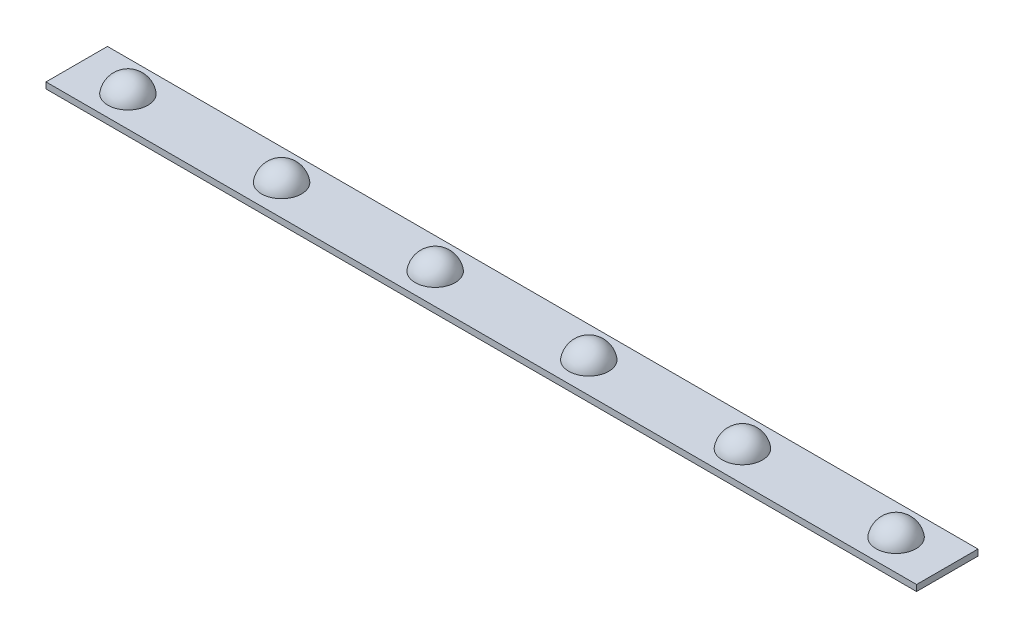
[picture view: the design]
ISO-10303-21;
HEADER;
FILE_DESCRIPTION(('STEP AP214'),'2;1');
FILE_NAME('part.step','',(''),(''),'','','');
FILE_SCHEMA(('AUTOMOTIVE_DESIGN { 1 0 10303 214 1 1 1 1 }'));
ENDSEC;
DATA;
#1=APPLICATION_CONTEXT('core data for automotive mechanical design processes');
#2=APPLICATION_PROTOCOL_DEFINITION('international standard','automotive_design',2000,#1);
#3=PRODUCT_CONTEXT('',#1,'mechanical');
#4=PRODUCT('Part','Part','',(#3));
#5=PRODUCT_RELATED_PRODUCT_CATEGORY('part','',(#4));
#6=PRODUCT_DEFINITION_FORMATION('','',#4);
#7=PRODUCT_DEFINITION_CONTEXT('part definition',#1,'design');
#8=PRODUCT_DEFINITION('design','',#6,#7);
#9=PRODUCT_DEFINITION_SHAPE('','',#8);
#10=(LENGTH_UNIT() NAMED_UNIT(*) SI_UNIT(.MILLI.,.METRE.));
#11=(NAMED_UNIT(*) PLANE_ANGLE_UNIT() SI_UNIT($,.RADIAN.));
#12=(NAMED_UNIT(*) SI_UNIT($,.STERADIAN.) SOLID_ANGLE_UNIT());
#13=UNCERTAINTY_MEASURE_WITH_UNIT(LENGTH_MEASURE(1.E-05),#10,'distance_accuracy_value','');
#14=(GEOMETRIC_REPRESENTATION_CONTEXT(3) GLOBAL_UNCERTAINTY_ASSIGNED_CONTEXT((#13)) GLOBAL_UNIT_ASSIGNED_CONTEXT((#10,
#11,#12)) REPRESENTATION_CONTEXT('',''));
#15=CARTESIAN_POINT('',(0.,0.,0.));
#16=DIRECTION('',(0.,0.,1.));
#17=DIRECTION('',(1.,0.,0.));
#18=AXIS2_PLACEMENT_3D('',#15,#16,#17);
#19=CARTESIAN_POINT('',(-243.713,-19.5553717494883,3.9624));
#20=DIRECTION('',(0.,1.,0.));
#21=DIRECTION('',(0.,0.,1.));
#22=AXIS2_PLACEMENT_3D('',#19,#20,#21);
#23=PLANE('',#22);
#24=CARTESIAN_POINT('',(-237.363,-19.5553717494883,2.63210155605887));
#25=CARTESIAN_POINT('',(-237.447190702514,-19.5553717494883,2.63210227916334));
#26=CARTESIAN_POINT('',(-237.531370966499,-19.5553717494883,2.62780900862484));
#27=CARTESIAN_POINT('',(-237.698898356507,-19.5553717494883,2.61069058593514));
#28=CARTESIAN_POINT('',(-237.782244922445,-19.5553717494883,2.5978600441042));
#29=CARTESIAN_POINT('',(-238.001164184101,-19.5553717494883,2.55261481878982));
#30=CARTESIAN_POINT('',(-238.135296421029,-19.5553717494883,2.51288252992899));
#31=CARTESIAN_POINT('',(-238.395079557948,-19.5553717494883,2.41143114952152));
#32=CARTESIAN_POINT('',(-238.520720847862,-19.5553717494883,2.3496876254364));
#33=CARTESIAN_POINT('',(-238.759809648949,-19.5553717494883,2.20600089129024));
#34=CARTESIAN_POINT('',(-238.873262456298,-19.5553717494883,2.12406650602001));
#35=CARTESIAN_POINT('',(-239.084770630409,-19.5553717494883,1.94233439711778));
#36=CARTESIAN_POINT('',(-239.18282968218,-19.5553717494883,1.84254096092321));
#37=CARTESIAN_POINT('',(-239.360814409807,-19.5553717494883,1.62789843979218));
#38=CARTESIAN_POINT('',(-239.440738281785,-19.5553717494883,1.51304785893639));
#39=CARTESIAN_POINT('',(-239.580172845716,-19.5553717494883,1.27155407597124));
#40=CARTESIAN_POINT('',(-239.639682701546,-19.5553717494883,1.14491039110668));
#41=CARTESIAN_POINT('',(-239.736594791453,-19.5553717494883,0.883432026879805));
#42=CARTESIAN_POINT('',(-239.77399744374,-19.5553717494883,0.748597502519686));
#43=CARTESIAN_POINT('',(-239.825634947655,-19.5553717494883,0.47456328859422));
#44=CARTESIAN_POINT('',(-239.839869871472,-19.5553717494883,0.335363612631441));
#45=CARTESIAN_POINT('',(-239.844768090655,-19.5553717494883,0.0565500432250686));
#46=CARTESIAN_POINT('',(-239.835431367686,-19.5553717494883,-0.0830638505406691));
#47=CARTESIAN_POINT('',(-239.793451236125,-19.5553717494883,-0.358742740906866));
#48=CARTESIAN_POINT('',(-239.760807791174,-19.5553717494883,-0.494807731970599));
#49=CARTESIAN_POINT('',(-239.673140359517,-19.5553717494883,-0.75952774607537));
#50=CARTESIAN_POINT('',(-239.61811609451,-19.5553717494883,-0.888182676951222));
#51=CARTESIAN_POINT('',(-239.487250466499,-19.5553717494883,-1.13442527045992));
#52=CARTESIAN_POINT('',(-239.411409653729,-19.5553717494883,-1.25201322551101));
#53=CARTESIAN_POINT('',(-239.241069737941,-19.5553717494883,-1.47278061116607));
#54=CARTESIAN_POINT('',(-239.146571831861,-19.5553717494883,-1.57596096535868));
#55=CARTESIAN_POINT('',(-238.941576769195,-19.5553717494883,-1.76500863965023));
#56=CARTESIAN_POINT('',(-238.831077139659,-19.5553717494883,-1.85087327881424));
#57=CARTESIAN_POINT('',(-238.597209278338,-19.5553717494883,-2.0028513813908));
#58=CARTESIAN_POINT('',(-238.473837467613,-19.5553717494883,-2.06895933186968));
#59=CARTESIAN_POINT('',(-238.217789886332,-19.5553717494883,-2.17947999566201));
#60=CARTESIAN_POINT('',(-238.085120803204,-19.5553717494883,-2.22390812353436));
#61=CARTESIAN_POINT('',(-237.853783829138,-19.5553717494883,-2.28025921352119));
#62=CARTESIAN_POINT('',(-237.75646039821,-19.5553717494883,-2.29787961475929));
#63=CARTESIAN_POINT('',(-237.560419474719,-19.5553717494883,-2.32139798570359));
#64=CARTESIAN_POINT('',(-237.461702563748,-19.5553717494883,-2.32730070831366));
#65=CARTESIAN_POINT('',(-237.278809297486,-19.5553717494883,-2.32730227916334));
#66=CARTESIAN_POINT('',(-237.194629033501,-19.5553717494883,-2.32300900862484));
#67=CARTESIAN_POINT('',(-237.027101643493,-19.5553717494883,-2.30589058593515));
#68=CARTESIAN_POINT('',(-236.943755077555,-19.5553717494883,-2.2930600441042));
#69=CARTESIAN_POINT('',(-236.724835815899,-19.5553717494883,-2.24781481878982));
#70=CARTESIAN_POINT('',(-236.590703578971,-19.5553717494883,-2.20808252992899));
#71=CARTESIAN_POINT('',(-236.330920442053,-19.5553717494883,-2.10663114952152));
#72=CARTESIAN_POINT('',(-236.205279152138,-19.5553717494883,-2.04488762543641));
#73=CARTESIAN_POINT('',(-235.966190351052,-19.5553717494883,-1.90120089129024));
#74=CARTESIAN_POINT('',(-235.852737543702,-19.5553717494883,-1.81926650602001));
#75=CARTESIAN_POINT('',(-235.641229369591,-19.5553717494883,-1.63753439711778));
#76=CARTESIAN_POINT('',(-235.54317031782,-19.5553717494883,-1.53774096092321));
#77=CARTESIAN_POINT('',(-235.365185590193,-19.5553717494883,-1.32309843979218));
#78=CARTESIAN_POINT('',(-235.285261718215,-19.5553717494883,-1.20824785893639));
#79=CARTESIAN_POINT('',(-235.145827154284,-19.5553717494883,-0.966754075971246));
#80=CARTESIAN_POINT('',(-235.086317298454,-19.5553717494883,-0.840110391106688));
#81=CARTESIAN_POINT('',(-234.989405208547,-19.5553717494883,-0.578632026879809));
#82=CARTESIAN_POINT('',(-234.952002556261,-19.5553717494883,-0.443797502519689));
#83=CARTESIAN_POINT('',(-234.900365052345,-19.5553717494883,-0.169763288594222));
#84=CARTESIAN_POINT('',(-234.886130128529,-19.5553717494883,-0.0305636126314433));
#85=CARTESIAN_POINT('',(-234.881231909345,-19.5553717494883,0.24824995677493));
#86=CARTESIAN_POINT('',(-234.890568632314,-19.5553717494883,0.387863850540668));
#87=CARTESIAN_POINT('',(-234.932548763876,-19.5553717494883,0.663542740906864));
#88=CARTESIAN_POINT('',(-234.965192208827,-19.5553717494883,0.799607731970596));
#89=CARTESIAN_POINT('',(-235.052859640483,-19.5553717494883,1.06432774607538));
#90=CARTESIAN_POINT('',(-235.10788390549,-19.5553717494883,1.19298267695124));
#91=CARTESIAN_POINT('',(-235.238749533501,-19.5553717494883,1.43922527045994));
#92=CARTESIAN_POINT('',(-235.314590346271,-19.5553717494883,1.55681322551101));
#93=CARTESIAN_POINT('',(-235.484930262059,-19.5553717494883,1.77758061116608));
#94=CARTESIAN_POINT('',(-235.579428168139,-19.5553717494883,1.88076096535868));
#95=CARTESIAN_POINT('',(-235.784423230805,-19.5553717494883,2.06980863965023));
#96=CARTESIAN_POINT('',(-235.894922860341,-19.5553717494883,2.15567327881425));
#97=CARTESIAN_POINT('',(-236.128790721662,-19.5553717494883,2.30765138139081));
#98=CARTESIAN_POINT('',(-236.252162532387,-19.5553717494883,2.37375933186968));
#99=CARTESIAN_POINT('',(-236.508210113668,-19.5553717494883,2.484279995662));
#100=CARTESIAN_POINT('',(-236.640879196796,-19.5553717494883,2.52870812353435));
#101=CARTESIAN_POINT('',(-236.872216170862,-19.5553717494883,2.58505921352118));
#102=CARTESIAN_POINT('',(-236.96953960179,-19.5553717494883,2.60267961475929));
#103=CARTESIAN_POINT('',(-237.165580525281,-19.5553717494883,2.62619798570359));
#104=CARTESIAN_POINT('',(-237.264297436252,-19.5553717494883,2.63210070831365));
#105=CARTESIAN_POINT('',(-237.363,-19.5553717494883,2.63210155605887));
#106=B_SPLINE_CURVE_WITH_KNOTS('',3,(#24,#25,#26,#27,#28,#29,#30,#31,#32,#33,#34,#35,#36,#37,
#38,#39,#40,#41,#42,#43,#44,#45,#46,#47,#48,#49,#50,#51,#52,#53,#54,#55,#56,#57,#58,#59,#60,#61,
#62,#63,#64,#65,#66,#67,#68,#69,#70,#71,#72,#73,#74,#75,#76,#77,#78,#79,#80,#81,#82,#83,#84,#85,
#86,#87,#88,#89,#90,#91,#92,#93,#94,#95,#96,#97,#98,#99,#100,#101,#102,#103,#104,#105),
.UNSPECIFIED.,.T.,.F.,(4,2,2,2,2,2,2,2,2,2,2,2,2,2,2,2,2,2,2,2,2,2,2,2,2,2,2,2,2,2,2,2,2,2,2,2,
2,2,2,2,4),(0.,0.252435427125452,0.505030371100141,0.922589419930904,1.34061341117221,
1.75845502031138,2.17619645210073,2.59397941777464,3.0117794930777,3.42957166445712,
3.8473625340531,4.26515372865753,4.6829455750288,5.10074261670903,5.51852861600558,
5.93628782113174,6.35411165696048,6.77205197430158,7.18969469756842,7.4857622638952,
7.7817097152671,8.03414514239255,8.28674008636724,8.70429913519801,9.12232312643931,
9.54016473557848,9.95790616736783,10.3756891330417,10.7934892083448,11.2112813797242,
11.6290722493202,12.0468634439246,12.4646552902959,12.8824523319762,13.3002383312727,
13.7179975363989,14.1358213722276,14.5537616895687,14.9714044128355,15.2674719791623,
15.5634194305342),.UNSPECIFIED.);
#107=CARTESIAN_POINT('',(-237.363,-19.5553717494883,2.63210155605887));
#108=VERTEX_POINT('',#107);
#109=EDGE_CURVE('E256',#108,#108,#106,.T.);
#110=ORIENTED_EDGE('',*,*,#109,.F.);
#111=EDGE_LOOP('',(#110));
#112=FACE_BOUND('',#111,.T.);
#113=CARTESIAN_POINT('',(-218.313,-19.5553717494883,-2.32730155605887));
#114=CARTESIAN_POINT('',(-218.228809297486,-19.5553717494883,-2.32730227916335));
#115=CARTESIAN_POINT('',(-218.144629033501,-19.5553717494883,-2.32300900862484));
#116=CARTESIAN_POINT('',(-217.977101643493,-19.5553717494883,-2.30589058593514));
#117=CARTESIAN_POINT('',(-217.893755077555,-19.5553717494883,-2.2930600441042));
#118=CARTESIAN_POINT('',(-217.674835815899,-19.5553717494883,-2.24781481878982));
#119=CARTESIAN_POINT('',(-217.540703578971,-19.5553717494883,-2.20808252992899));
#120=CARTESIAN_POINT('',(-217.280920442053,-19.5553717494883,-2.10663114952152));
#121=CARTESIAN_POINT('',(-217.155279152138,-19.5553717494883,-2.0448876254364));
#122=CARTESIAN_POINT('',(-216.916190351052,-19.5553717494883,-1.90120089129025));
#123=CARTESIAN_POINT('',(-216.802737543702,-19.5553717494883,-1.81926650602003));
#124=CARTESIAN_POINT('',(-216.591229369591,-19.5553717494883,-1.6375343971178));
#125=CARTESIAN_POINT('',(-216.49317031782,-19.5553717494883,-1.53774096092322));
#126=CARTESIAN_POINT('',(-216.315185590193,-19.5553717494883,-1.32309843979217));
#127=CARTESIAN_POINT('',(-216.235261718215,-19.5553717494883,-1.20824785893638));
#128=CARTESIAN_POINT('',(-216.095827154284,-19.5553717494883,-0.966754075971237));
#129=CARTESIAN_POINT('',(-216.036317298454,-19.5553717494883,-0.840110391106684));
#130=CARTESIAN_POINT('',(-215.939405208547,-19.5553717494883,-0.578632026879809));
#131=CARTESIAN_POINT('',(-215.902002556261,-19.5553717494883,-0.443797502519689));
#132=CARTESIAN_POINT('',(-215.850365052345,-19.5553717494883,-0.169763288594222));
#133=CARTESIAN_POINT('',(-215.836130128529,-19.5553717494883,-0.0305636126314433));
#134=CARTESIAN_POINT('',(-215.831231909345,-19.5553717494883,0.248249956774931));
#135=CARTESIAN_POINT('',(-215.840568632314,-19.5553717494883,0.387863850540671));
#136=CARTESIAN_POINT('',(-215.882548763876,-19.5553717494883,0.663542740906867));
#137=CARTESIAN_POINT('',(-215.915192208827,-19.5553717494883,0.799607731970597));
#138=CARTESIAN_POINT('',(-216.002859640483,-19.5553717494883,1.06432774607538));
#139=CARTESIAN_POINT('',(-216.05788390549,-19.5553717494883,1.19298267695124));
#140=CARTESIAN_POINT('',(-216.188749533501,-19.5553717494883,1.43922527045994));
#141=CARTESIAN_POINT('',(-216.264590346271,-19.5553717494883,1.55681322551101));
#142=CARTESIAN_POINT('',(-216.434930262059,-19.5553717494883,1.77758061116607));
#143=CARTESIAN_POINT('',(-216.529428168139,-19.5553717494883,1.88076096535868));
#144=CARTESIAN_POINT('',(-216.734423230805,-19.5553717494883,2.06980863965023));
#145=CARTESIAN_POINT('',(-216.844922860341,-19.5553717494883,2.15567327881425));
#146=CARTESIAN_POINT('',(-217.078790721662,-19.5553717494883,2.30765138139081));
#147=CARTESIAN_POINT('',(-217.202162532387,-19.5553717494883,2.37375933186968));
#148=CARTESIAN_POINT('',(-217.458210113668,-19.5553717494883,2.484279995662));
#149=CARTESIAN_POINT('',(-217.590879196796,-19.5553717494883,2.52870812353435));
#150=CARTESIAN_POINT('',(-217.822216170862,-19.5553717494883,2.58505921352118));
#151=CARTESIAN_POINT('',(-217.91953960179,-19.5553717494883,2.60267961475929));
#152=CARTESIAN_POINT('',(-218.115580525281,-19.5553717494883,2.62619798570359));
#153=CARTESIAN_POINT('',(-218.214297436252,-19.5553717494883,2.63210070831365));
#154=CARTESIAN_POINT('',(-218.397190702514,-19.5553717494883,2.63210227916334));
#155=CARTESIAN_POINT('',(-218.481370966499,-19.5553717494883,2.62780900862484));
#156=CARTESIAN_POINT('',(-218.648898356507,-19.5553717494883,2.61069058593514));
#157=CARTESIAN_POINT('',(-218.732244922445,-19.5553717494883,2.5978600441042));
#158=CARTESIAN_POINT('',(-218.951164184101,-19.5553717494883,2.55261481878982));
#159=CARTESIAN_POINT('',(-219.085296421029,-19.5553717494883,2.51288252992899));
#160=CARTESIAN_POINT('',(-219.345079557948,-19.5553717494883,2.41143114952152));
#161=CARTESIAN_POINT('',(-219.470720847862,-19.5553717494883,2.3496876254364));
#162=CARTESIAN_POINT('',(-219.709809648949,-19.5553717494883,2.20600089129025));
#163=CARTESIAN_POINT('',(-219.823262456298,-19.5553717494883,2.12406650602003));
#164=CARTESIAN_POINT('',(-220.034770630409,-19.5553717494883,1.9423343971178));
#165=CARTESIAN_POINT('',(-220.13282968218,-19.5553717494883,1.84254096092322));
#166=CARTESIAN_POINT('',(-220.310814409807,-19.5553717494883,1.62789843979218));
#167=CARTESIAN_POINT('',(-220.390738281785,-19.5553717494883,1.5130478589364));
#168=CARTESIAN_POINT('',(-220.530172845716,-19.5553717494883,1.27155407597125));
#169=CARTESIAN_POINT('',(-220.589682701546,-19.5553717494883,1.14491039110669));
#170=CARTESIAN_POINT('',(-220.686594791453,-19.5553717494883,0.883432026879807));
#171=CARTESIAN_POINT('',(-220.72399744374,-19.5553717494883,0.748597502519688));
#172=CARTESIAN_POINT('',(-220.775634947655,-19.5553717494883,0.474563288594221));
#173=CARTESIAN_POINT('',(-220.789869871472,-19.5553717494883,0.335363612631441));
#174=CARTESIAN_POINT('',(-220.794768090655,-19.5553717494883,0.0565500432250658));
#175=CARTESIAN_POINT('',(-220.785431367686,-19.5553717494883,-0.0830638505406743));
#176=CARTESIAN_POINT('',(-220.743451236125,-19.5553717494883,-0.35874274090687));
#177=CARTESIAN_POINT('',(-220.710807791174,-19.5553717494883,-0.4948077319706));
#178=CARTESIAN_POINT('',(-220.623140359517,-19.5553717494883,-0.759527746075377));
#179=CARTESIAN_POINT('',(-220.56811609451,-19.5553717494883,-0.888182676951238));
#180=CARTESIAN_POINT('',(-220.437250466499,-19.5553717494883,-1.13442527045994));
#181=CARTESIAN_POINT('',(-220.361409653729,-19.5553717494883,-1.25201322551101));
#182=CARTESIAN_POINT('',(-220.191069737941,-19.5553717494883,-1.47278061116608));
#183=CARTESIAN_POINT('',(-220.096571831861,-19.5553717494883,-1.57596096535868));
#184=CARTESIAN_POINT('',(-219.891576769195,-19.5553717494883,-1.76500863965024));
#185=CARTESIAN_POINT('',(-219.781077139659,-19.5553717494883,-1.85087327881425));
#186=CARTESIAN_POINT('',(-219.547209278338,-19.5553717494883,-2.00285138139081));
#187=CARTESIAN_POINT('',(-219.423837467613,-19.5553717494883,-2.06895933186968));
#188=CARTESIAN_POINT('',(-219.167789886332,-19.5553717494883,-2.17947999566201));
#189=CARTESIAN_POINT('',(-219.035120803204,-19.5553717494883,-2.22390812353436));
#190=CARTESIAN_POINT('',(-218.803783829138,-19.5553717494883,-2.28025921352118));
#191=CARTESIAN_POINT('',(-218.70646039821,-19.5553717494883,-2.29787961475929));
#192=CARTESIAN_POINT('',(-218.510419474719,-19.5553717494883,-2.32139798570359));
#193=CARTESIAN_POINT('',(-218.411702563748,-19.5553717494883,-2.32730070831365));
#194=CARTESIAN_POINT('',(-218.313,-19.5553717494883,-2.32730155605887));
#195=B_SPLINE_CURVE_WITH_KNOTS('',3,(#113,#114,#115,#116,#117,#118,#119,#120,#121,#122,#123,
#124,#125,#126,#127,#128,#129,#130,#131,#132,#133,#134,#135,#136,#137,#138,#139,#140,#141,#142,
#143,#144,#145,#146,#147,#148,#149,#150,#151,#152,#153,#154,#155,#156,#157,#158,#159,#160,#161,
#162,#163,#164,#165,#166,#167,#168,#169,#170,#171,#172,#173,#174,#175,#176,#177,#178,#179,#180,
#181,#182,#183,#184,#185,#186,#187,#188,#189,#190,#191,#192,#193,#194),.UNSPECIFIED.,.T.,.F.,(4,
2,2,2,2,2,2,2,2,2,2,2,2,2,2,2,2,2,2,2,2,2,2,2,2,2,2,2,2,2,2,2,2,2,2,2,2,2,2,2,4),(0.,
0.25243542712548,0.505030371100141,0.922589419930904,1.34061341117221,1.75845502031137,
2.17619645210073,2.59397941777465,3.0117794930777,3.42957166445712,3.8473625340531,
4.26515372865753,4.6829455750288,5.10074261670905,5.5185286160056,5.93628782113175,
6.35411165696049,6.77205197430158,7.18969469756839,7.48576226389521,7.7817097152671,
8.03414514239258,8.28674008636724,8.70429913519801,9.12232312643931,9.54016473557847,
9.95790616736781,10.3756891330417,10.7934892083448,11.2112813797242,11.6290722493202,
12.0468634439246,12.4646552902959,12.8824523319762,13.3002383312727,13.7179975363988,
14.1358213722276,14.5537616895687,14.9714044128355,15.2674719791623,15.5634194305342),.UNSPECIFIED.);
#196=CARTESIAN_POINT('',(-218.313,-19.5553717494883,-2.32730155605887));
#197=VERTEX_POINT('',#196);
#198=EDGE_CURVE('E293',#197,#197,#195,.T.);
#199=ORIENTED_EDGE('',*,*,#198,.F.);
#200=EDGE_LOOP('',(#199));
#201=FACE_BOUND('',#200,.T.);
#202=CARTESIAN_POINT('',(-199.263,-19.5553717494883,-2.32730155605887));
#203=CARTESIAN_POINT('',(-199.178809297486,-19.5553717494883,-2.32730227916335));
#204=CARTESIAN_POINT('',(-199.094629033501,-19.5553717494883,-2.32300900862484));
#205=CARTESIAN_POINT('',(-198.927101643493,-19.5553717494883,-2.30589058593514));
#206=CARTESIAN_POINT('',(-198.843755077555,-19.5553717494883,-2.2930600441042));
#207=CARTESIAN_POINT('',(-198.624835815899,-19.5553717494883,-2.24781481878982));
#208=CARTESIAN_POINT('',(-198.490703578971,-19.5553717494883,-2.20808252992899));
#209=CARTESIAN_POINT('',(-198.230920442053,-19.5553717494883,-2.10663114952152));
#210=CARTESIAN_POINT('',(-198.105279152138,-19.5553717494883,-2.0448876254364));
#211=CARTESIAN_POINT('',(-197.866190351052,-19.5553717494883,-1.90120089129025));
#212=CARTESIAN_POINT('',(-197.752737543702,-19.5553717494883,-1.81926650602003));
#213=CARTESIAN_POINT('',(-197.541229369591,-19.5553717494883,-1.6375343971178));
#214=CARTESIAN_POINT('',(-197.44317031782,-19.5553717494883,-1.53774096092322));
#215=CARTESIAN_POINT('',(-197.265185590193,-19.5553717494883,-1.32309843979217));
#216=CARTESIAN_POINT('',(-197.185261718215,-19.5553717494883,-1.20824785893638));
#217=CARTESIAN_POINT('',(-197.045827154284,-19.5553717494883,-0.966754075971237));
#218=CARTESIAN_POINT('',(-196.986317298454,-19.5553717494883,-0.840110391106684));
#219=CARTESIAN_POINT('',(-196.889405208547,-19.5553717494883,-0.578632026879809));
#220=CARTESIAN_POINT('',(-196.852002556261,-19.5553717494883,-0.443797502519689));
#221=CARTESIAN_POINT('',(-196.800365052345,-19.5553717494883,-0.169763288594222));
#222=CARTESIAN_POINT('',(-196.786130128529,-19.5553717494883,-0.0305636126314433));
#223=CARTESIAN_POINT('',(-196.781231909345,-19.5553717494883,0.248249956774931));
#224=CARTESIAN_POINT('',(-196.790568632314,-19.5553717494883,0.387863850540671));
#225=CARTESIAN_POINT('',(-196.832548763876,-19.5553717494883,0.663542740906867));
#226=CARTESIAN_POINT('',(-196.865192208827,-19.5553717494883,0.799607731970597));
#227=CARTESIAN_POINT('',(-196.952859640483,-19.5553717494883,1.06432774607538));
#228=CARTESIAN_POINT('',(-197.00788390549,-19.5553717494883,1.19298267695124));
#229=CARTESIAN_POINT('',(-197.138749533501,-19.5553717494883,1.43922527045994));
#230=CARTESIAN_POINT('',(-197.214590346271,-19.5553717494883,1.55681322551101));
#231=CARTESIAN_POINT('',(-197.384930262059,-19.5553717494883,1.77758061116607));
#232=CARTESIAN_POINT('',(-197.479428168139,-19.5553717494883,1.88076096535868));
#233=CARTESIAN_POINT('',(-197.684423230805,-19.5553717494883,2.06980863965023));
#234=CARTESIAN_POINT('',(-197.794922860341,-19.5553717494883,2.15567327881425));
#235=CARTESIAN_POINT('',(-198.028790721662,-19.5553717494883,2.30765138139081));
#236=CARTESIAN_POINT('',(-198.152162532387,-19.5553717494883,2.37375933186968));
#237=CARTESIAN_POINT('',(-198.408210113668,-19.5553717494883,2.484279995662));
#238=CARTESIAN_POINT('',(-198.540879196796,-19.5553717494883,2.52870812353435));
#239=CARTESIAN_POINT('',(-198.772216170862,-19.5553717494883,2.58505921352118));
#240=CARTESIAN_POINT('',(-198.86953960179,-19.5553717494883,2.60267961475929));
#241=CARTESIAN_POINT('',(-199.065580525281,-19.5553717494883,2.62619798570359));
#242=CARTESIAN_POINT('',(-199.164297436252,-19.5553717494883,2.63210070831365));
#243=CARTESIAN_POINT('',(-199.347190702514,-19.5553717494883,2.63210227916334));
#244=CARTESIAN_POINT('',(-199.431370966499,-19.5553717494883,2.62780900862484));
#245=CARTESIAN_POINT('',(-199.598898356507,-19.5553717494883,2.61069058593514));
#246=CARTESIAN_POINT('',(-199.682244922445,-19.5553717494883,2.5978600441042));
#247=CARTESIAN_POINT('',(-199.901164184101,-19.5553717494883,2.55261481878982));
#248=CARTESIAN_POINT('',(-200.035296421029,-19.5553717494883,2.51288252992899));
#249=CARTESIAN_POINT('',(-200.295079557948,-19.5553717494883,2.41143114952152));
#250=CARTESIAN_POINT('',(-200.420720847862,-19.5553717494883,2.3496876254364));
#251=CARTESIAN_POINT('',(-200.659809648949,-19.5553717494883,2.20600089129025));
#252=CARTESIAN_POINT('',(-200.773262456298,-19.5553717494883,2.12406650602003));
#253=CARTESIAN_POINT('',(-200.984770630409,-19.5553717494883,1.9423343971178));
#254=CARTESIAN_POINT('',(-201.08282968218,-19.5553717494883,1.84254096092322));
#255=CARTESIAN_POINT('',(-201.260814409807,-19.5553717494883,1.62789843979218));
#256=CARTESIAN_POINT('',(-201.340738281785,-19.5553717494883,1.5130478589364));
#257=CARTESIAN_POINT('',(-201.480172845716,-19.5553717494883,1.27155407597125));
#258=CARTESIAN_POINT('',(-201.539682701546,-19.5553717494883,1.14491039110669));
#259=CARTESIAN_POINT('',(-201.636594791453,-19.5553717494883,0.883432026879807));
#260=CARTESIAN_POINT('',(-201.67399744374,-19.5553717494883,0.748597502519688));
#261=CARTESIAN_POINT('',(-201.725634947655,-19.5553717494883,0.474563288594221));
#262=CARTESIAN_POINT('',(-201.739869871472,-19.5553717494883,0.335363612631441));
#263=CARTESIAN_POINT('',(-201.744768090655,-19.5553717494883,0.0565500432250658));
#264=CARTESIAN_POINT('',(-201.735431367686,-19.5553717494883,-0.0830638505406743));
#265=CARTESIAN_POINT('',(-201.693451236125,-19.5553717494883,-0.35874274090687));
#266=CARTESIAN_POINT('',(-201.660807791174,-19.5553717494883,-0.4948077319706));
#267=CARTESIAN_POINT('',(-201.573140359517,-19.5553717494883,-0.759527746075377));
#268=CARTESIAN_POINT('',(-201.51811609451,-19.5553717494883,-0.888182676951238));
#269=CARTESIAN_POINT('',(-201.387250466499,-19.5553717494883,-1.13442527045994));
#270=CARTESIAN_POINT('',(-201.311409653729,-19.5553717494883,-1.25201322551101));
#271=CARTESIAN_POINT('',(-201.141069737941,-19.5553717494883,-1.47278061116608));
#272=CARTESIAN_POINT('',(-201.046571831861,-19.5553717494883,-1.57596096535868));
#273=CARTESIAN_POINT('',(-200.841576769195,-19.5553717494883,-1.76500863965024));
#274=CARTESIAN_POINT('',(-200.731077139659,-19.5553717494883,-1.85087327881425));
#275=CARTESIAN_POINT('',(-200.497209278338,-19.5553717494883,-2.00285138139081));
#276=CARTESIAN_POINT('',(-200.373837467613,-19.5553717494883,-2.06895933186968));
#277=CARTESIAN_POINT('',(-200.117789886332,-19.5553717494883,-2.17947999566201));
#278=CARTESIAN_POINT('',(-199.985120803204,-19.5553717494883,-2.22390812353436));
#279=CARTESIAN_POINT('',(-199.753783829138,-19.5553717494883,-2.28025921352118));
#280=CARTESIAN_POINT('',(-199.65646039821,-19.5553717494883,-2.29787961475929));
#281=CARTESIAN_POINT('',(-199.460419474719,-19.5553717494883,-2.32139798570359));
#282=CARTESIAN_POINT('',(-199.361702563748,-19.5553717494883,-2.32730070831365));
#283=CARTESIAN_POINT('',(-199.263,-19.5553717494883,-2.32730155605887));
#284=B_SPLINE_CURVE_WITH_KNOTS('',3,(#202,#203,#204,#205,#206,#207,#208,#209,#210,#211,#212,
#213,#214,#215,#216,#217,#218,#219,#220,#221,#222,#223,#224,#225,#226,#227,#228,#229,#230,#231,
#232,#233,#234,#235,#236,#237,#238,#239,#240,#241,#242,#243,#244,#245,#246,#247,#248,#249,#250,
#251,#252,#253,#254,#255,#256,#257,#258,#259,#260,#261,#262,#263,#264,#265,#266,#267,#268,#269,
#270,#271,#272,#273,#274,#275,#276,#277,#278,#279,#280,#281,#282,#283),.UNSPECIFIED.,.T.,.F.,(4,
2,2,2,2,2,2,2,2,2,2,2,2,2,2,2,2,2,2,2,2,2,2,2,2,2,2,2,2,2,2,2,2,2,2,2,2,2,2,2,4),(0.,
0.25243542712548,0.505030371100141,0.922589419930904,1.34061341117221,1.75845502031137,
2.17619645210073,2.59397941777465,3.0117794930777,3.42957166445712,3.8473625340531,
4.26515372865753,4.6829455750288,5.10074261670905,5.5185286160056,5.93628782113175,
6.35411165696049,6.77205197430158,7.18969469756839,7.48576226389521,7.7817097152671,
8.03414514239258,8.28674008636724,8.70429913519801,9.12232312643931,9.54016473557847,
9.95790616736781,10.3756891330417,10.7934892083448,11.2112813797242,11.6290722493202,
12.0468634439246,12.4646552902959,12.8824523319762,13.3002383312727,13.7179975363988,
14.1358213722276,14.5537616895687,14.9714044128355,15.2674719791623,15.5634194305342),.UNSPECIFIED.);
#285=CARTESIAN_POINT('',(-199.263,-19.5553717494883,-2.32730155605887));
#286=VERTEX_POINT('',#285);
#287=EDGE_CURVE('E250',#286,#286,#284,.T.);
#288=ORIENTED_EDGE('',*,*,#287,.F.);
#289=EDGE_LOOP('',(#288));
#290=FACE_BOUND('',#289,.T.);
#291=CARTESIAN_POINT('',(-180.213,-19.5553717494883,-2.32730155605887));
#292=CARTESIAN_POINT('',(-180.128809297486,-19.5553717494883,-2.32730227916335));
#293=CARTESIAN_POINT('',(-180.044629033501,-19.5553717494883,-2.32300900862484));
#294=CARTESIAN_POINT('',(-179.877101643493,-19.5553717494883,-2.30589058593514));
#295=CARTESIAN_POINT('',(-179.793755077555,-19.5553717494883,-2.2930600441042));
#296=CARTESIAN_POINT('',(-179.574835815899,-19.5553717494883,-2.24781481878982));
#297=CARTESIAN_POINT('',(-179.440703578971,-19.5553717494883,-2.20808252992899));
#298=CARTESIAN_POINT('',(-179.180920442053,-19.5553717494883,-2.10663114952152));
#299=CARTESIAN_POINT('',(-179.055279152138,-19.5553717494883,-2.0448876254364));
#300=CARTESIAN_POINT('',(-178.816190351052,-19.5553717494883,-1.90120089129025));
#301=CARTESIAN_POINT('',(-178.702737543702,-19.5553717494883,-1.81926650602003));
#302=CARTESIAN_POINT('',(-178.491229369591,-19.5553717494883,-1.6375343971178));
#303=CARTESIAN_POINT('',(-178.39317031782,-19.5553717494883,-1.53774096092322));
#304=CARTESIAN_POINT('',(-178.215185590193,-19.5553717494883,-1.32309843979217));
#305=CARTESIAN_POINT('',(-178.135261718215,-19.5553717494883,-1.20824785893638));
#306=CARTESIAN_POINT('',(-177.995827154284,-19.5553717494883,-0.966754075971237));
#307=CARTESIAN_POINT('',(-177.936317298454,-19.5553717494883,-0.840110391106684));
#308=CARTESIAN_POINT('',(-177.839405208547,-19.5553717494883,-0.578632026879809));
#309=CARTESIAN_POINT('',(-177.802002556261,-19.5553717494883,-0.443797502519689));
#310=CARTESIAN_POINT('',(-177.750365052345,-19.5553717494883,-0.169763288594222));
#311=CARTESIAN_POINT('',(-177.736130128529,-19.5553717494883,-0.0305636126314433));
#312=CARTESIAN_POINT('',(-177.731231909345,-19.5553717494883,0.248249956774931));
#313=CARTESIAN_POINT('',(-177.740568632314,-19.5553717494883,0.387863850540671));
#314=CARTESIAN_POINT('',(-177.782548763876,-19.5553717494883,0.663542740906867));
#315=CARTESIAN_POINT('',(-177.815192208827,-19.5553717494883,0.799607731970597));
#316=CARTESIAN_POINT('',(-177.902859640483,-19.5553717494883,1.06432774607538));
#317=CARTESIAN_POINT('',(-177.95788390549,-19.5553717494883,1.19298267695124));
#318=CARTESIAN_POINT('',(-178.088749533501,-19.5553717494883,1.43922527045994));
#319=CARTESIAN_POINT('',(-178.164590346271,-19.5553717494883,1.55681322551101));
#320=CARTESIAN_POINT('',(-178.334930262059,-19.5553717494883,1.77758061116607));
#321=CARTESIAN_POINT('',(-178.429428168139,-19.5553717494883,1.88076096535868));
#322=CARTESIAN_POINT('',(-178.634423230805,-19.5553717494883,2.06980863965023));
#323=CARTESIAN_POINT('',(-178.744922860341,-19.5553717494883,2.15567327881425));
#324=CARTESIAN_POINT('',(-178.978790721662,-19.5553717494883,2.30765138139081));
#325=CARTESIAN_POINT('',(-179.102162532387,-19.5553717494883,2.37375933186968));
#326=CARTESIAN_POINT('',(-179.358210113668,-19.5553717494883,2.484279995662));
#327=CARTESIAN_POINT('',(-179.490879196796,-19.5553717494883,2.52870812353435));
#328=CARTESIAN_POINT('',(-179.722216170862,-19.5553717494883,2.58505921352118));
#329=CARTESIAN_POINT('',(-179.81953960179,-19.5553717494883,2.60267961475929));
#330=CARTESIAN_POINT('',(-180.015580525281,-19.5553717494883,2.62619798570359));
#331=CARTESIAN_POINT('',(-180.114297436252,-19.5553717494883,2.63210070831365));
#332=CARTESIAN_POINT('',(-180.297190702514,-19.5553717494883,2.63210227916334));
#333=CARTESIAN_POINT('',(-180.381370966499,-19.5553717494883,2.62780900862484));
#334=CARTESIAN_POINT('',(-180.548898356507,-19.5553717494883,2.61069058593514));
#335=CARTESIAN_POINT('',(-180.632244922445,-19.5553717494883,2.5978600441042));
#336=CARTESIAN_POINT('',(-180.851164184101,-19.5553717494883,2.55261481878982));
#337=CARTESIAN_POINT('',(-180.985296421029,-19.5553717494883,2.51288252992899));
#338=CARTESIAN_POINT('',(-181.245079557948,-19.5553717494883,2.41143114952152));
#339=CARTESIAN_POINT('',(-181.370720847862,-19.5553717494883,2.3496876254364));
#340=CARTESIAN_POINT('',(-181.609809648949,-19.5553717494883,2.20600089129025));
#341=CARTESIAN_POINT('',(-181.723262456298,-19.5553717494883,2.12406650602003));
#342=CARTESIAN_POINT('',(-181.934770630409,-19.5553717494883,1.9423343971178));
#343=CARTESIAN_POINT('',(-182.03282968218,-19.5553717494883,1.84254096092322));
#344=CARTESIAN_POINT('',(-182.210814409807,-19.5553717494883,1.62789843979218));
#345=CARTESIAN_POINT('',(-182.290738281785,-19.5553717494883,1.5130478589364));
#346=CARTESIAN_POINT('',(-182.430172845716,-19.5553717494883,1.27155407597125));
#347=CARTESIAN_POINT('',(-182.489682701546,-19.5553717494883,1.14491039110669));
#348=CARTESIAN_POINT('',(-182.586594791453,-19.5553717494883,0.883432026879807));
#349=CARTESIAN_POINT('',(-182.62399744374,-19.5553717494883,0.748597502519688));
#350=CARTESIAN_POINT('',(-182.675634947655,-19.5553717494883,0.474563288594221));
#351=CARTESIAN_POINT('',(-182.689869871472,-19.5553717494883,0.335363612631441));
#352=CARTESIAN_POINT('',(-182.694768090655,-19.5553717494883,0.0565500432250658));
#353=CARTESIAN_POINT('',(-182.685431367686,-19.5553717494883,-0.0830638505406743));
#354=CARTESIAN_POINT('',(-182.643451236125,-19.5553717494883,-0.35874274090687));
#355=CARTESIAN_POINT('',(-182.610807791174,-19.5553717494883,-0.4948077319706));
#356=CARTESIAN_POINT('',(-182.523140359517,-19.5553717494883,-0.759527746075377));
#357=CARTESIAN_POINT('',(-182.46811609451,-19.5553717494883,-0.888182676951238));
#358=CARTESIAN_POINT('',(-182.337250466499,-19.5553717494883,-1.13442527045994));
#359=CARTESIAN_POINT('',(-182.261409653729,-19.5553717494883,-1.25201322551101));
#360=CARTESIAN_POINT('',(-182.091069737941,-19.5553717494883,-1.47278061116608));
#361=CARTESIAN_POINT('',(-181.996571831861,-19.5553717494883,-1.57596096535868));
#362=CARTESIAN_POINT('',(-181.791576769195,-19.5553717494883,-1.76500863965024));
#363=CARTESIAN_POINT('',(-181.681077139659,-19.5553717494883,-1.85087327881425));
#364=CARTESIAN_POINT('',(-181.447209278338,-19.5553717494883,-2.00285138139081));
#365=CARTESIAN_POINT('',(-181.323837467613,-19.5553717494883,-2.06895933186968));
#366=CARTESIAN_POINT('',(-181.067789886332,-19.5553717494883,-2.17947999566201));
#367=CARTESIAN_POINT('',(-180.935120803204,-19.5553717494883,-2.22390812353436));
#368=CARTESIAN_POINT('',(-180.703783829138,-19.5553717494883,-2.28025921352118));
#369=CARTESIAN_POINT('',(-180.60646039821,-19.5553717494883,-2.29787961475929));
#370=CARTESIAN_POINT('',(-180.410419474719,-19.5553717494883,-2.32139798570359));
#371=CARTESIAN_POINT('',(-180.311702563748,-19.5553717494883,-2.32730070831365));
#372=CARTESIAN_POINT('',(-180.213,-19.5553717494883,-2.32730155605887));
#373=B_SPLINE_CURVE_WITH_KNOTS('',3,(#291,#292,#293,#294,#295,#296,#297,#298,#299,#300,#301,
#302,#303,#304,#305,#306,#307,#308,#309,#310,#311,#312,#313,#314,#315,#316,#317,#318,#319,#320,
#321,#322,#323,#324,#325,#326,#327,#328,#329,#330,#331,#332,#333,#334,#335,#336,#337,#338,#339,
#340,#341,#342,#343,#344,#345,#346,#347,#348,#349,#350,#351,#352,#353,#354,#355,#356,#357,#358,
#359,#360,#361,#362,#363,#364,#365,#366,#367,#368,#369,#370,#371,#372),.UNSPECIFIED.,.T.,.F.,(4,
2,2,2,2,2,2,2,2,2,2,2,2,2,2,2,2,2,2,2,2,2,2,2,2,2,2,2,2,2,2,2,2,2,2,2,2,2,2,2,4),(0.,
0.25243542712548,0.505030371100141,0.922589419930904,1.34061341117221,1.75845502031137,
2.17619645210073,2.59397941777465,3.0117794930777,3.42957166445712,3.8473625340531,
4.26515372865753,4.6829455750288,5.10074261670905,5.5185286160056,5.93628782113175,
6.35411165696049,6.77205197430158,7.18969469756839,7.48576226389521,7.7817097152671,
8.03414514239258,8.28674008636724,8.70429913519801,9.12232312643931,9.54016473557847,
9.95790616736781,10.3756891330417,10.7934892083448,11.2112813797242,11.6290722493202,
12.0468634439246,12.4646552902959,12.8824523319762,13.3002383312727,13.7179975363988,
14.1358213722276,14.5537616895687,14.9714044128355,15.2674719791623,15.5634194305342),.UNSPECIFIED.);
#374=CARTESIAN_POINT('',(-180.213,-19.5553717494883,-2.32730155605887));
#375=VERTEX_POINT('',#374);
#376=EDGE_CURVE('E289',#375,#375,#373,.T.);
#377=ORIENTED_EDGE('',*,*,#376,.F.);
#378=EDGE_LOOP('',(#377));
#379=FACE_BOUND('',#378,.T.);
#380=CARTESIAN_POINT('',(-161.163,-19.5553717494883,-2.32730155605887));
#381=CARTESIAN_POINT('',(-161.078809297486,-19.5553717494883,-2.32730227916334));
#382=CARTESIAN_POINT('',(-160.994629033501,-19.5553717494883,-2.32300900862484));
#383=CARTESIAN_POINT('',(-160.827101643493,-19.5553717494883,-2.30589058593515));
#384=CARTESIAN_POINT('',(-160.743755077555,-19.5553717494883,-2.2930600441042));
#385=CARTESIAN_POINT('',(-160.524835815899,-19.5553717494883,-2.24781481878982));
#386=CARTESIAN_POINT('',(-160.390703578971,-19.5553717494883,-2.20808252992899));
#387=CARTESIAN_POINT('',(-160.130920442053,-19.5553717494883,-2.10663114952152));
#388=CARTESIAN_POINT('',(-160.005279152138,-19.5553717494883,-2.04488762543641));
#389=CARTESIAN_POINT('',(-159.766190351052,-19.5553717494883,-1.90120089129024));
#390=CARTESIAN_POINT('',(-159.652737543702,-19.5553717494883,-1.81926650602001));
#391=CARTESIAN_POINT('',(-159.441229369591,-19.5553717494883,-1.63753439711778));
#392=CARTESIAN_POINT('',(-159.34317031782,-19.5553717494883,-1.53774096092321));
#393=CARTESIAN_POINT('',(-159.165185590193,-19.5553717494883,-1.32309843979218));
#394=CARTESIAN_POINT('',(-159.085261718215,-19.5553717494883,-1.20824785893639));
#395=CARTESIAN_POINT('',(-158.945827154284,-19.5553717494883,-0.966754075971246));
#396=CARTESIAN_POINT('',(-158.886317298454,-19.5553717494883,-0.840110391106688));
#397=CARTESIAN_POINT('',(-158.789405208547,-19.5553717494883,-0.578632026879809));
#398=CARTESIAN_POINT('',(-158.752002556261,-19.5553717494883,-0.443797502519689));
#399=CARTESIAN_POINT('',(-158.700365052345,-19.5553717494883,-0.169763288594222));
#400=CARTESIAN_POINT('',(-158.686130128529,-19.5553717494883,-0.0305636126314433));
#401=CARTESIAN_POINT('',(-158.681231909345,-19.5553717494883,0.24824995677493));
#402=CARTESIAN_POINT('',(-158.690568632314,-19.5553717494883,0.387863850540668));
#403=CARTESIAN_POINT('',(-158.732548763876,-19.5553717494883,0.663542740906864));
#404=CARTESIAN_POINT('',(-158.765192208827,-19.5553717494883,0.799607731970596));
#405=CARTESIAN_POINT('',(-158.852859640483,-19.5553717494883,1.06432774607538));
#406=CARTESIAN_POINT('',(-158.90788390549,-19.5553717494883,1.19298267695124));
#407=CARTESIAN_POINT('',(-159.038749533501,-19.5553717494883,1.43922527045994));
#408=CARTESIAN_POINT('',(-159.114590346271,-19.5553717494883,1.55681322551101));
#409=CARTESIAN_POINT('',(-159.284930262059,-19.5553717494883,1.77758061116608));
#410=CARTESIAN_POINT('',(-159.379428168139,-19.5553717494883,1.88076096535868));
#411=CARTESIAN_POINT('',(-159.584423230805,-19.5553717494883,2.06980863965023));
#412=CARTESIAN_POINT('',(-159.694922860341,-19.5553717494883,2.15567327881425));
#413=CARTESIAN_POINT('',(-159.928790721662,-19.5553717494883,2.30765138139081));
#414=CARTESIAN_POINT('',(-160.052162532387,-19.5553717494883,2.37375933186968));
#415=CARTESIAN_POINT('',(-160.308210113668,-19.5553717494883,2.484279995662));
#416=CARTESIAN_POINT('',(-160.440879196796,-19.5553717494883,2.52870812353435));
#417=CARTESIAN_POINT('',(-160.672216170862,-19.5553717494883,2.58505921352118));
#418=CARTESIAN_POINT('',(-160.76953960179,-19.5553717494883,2.60267961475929));
#419=CARTESIAN_POINT('',(-160.965580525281,-19.5553717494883,2.62619798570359));
#420=CARTESIAN_POINT('',(-161.064297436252,-19.5553717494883,2.63210070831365));
#421=CARTESIAN_POINT('',(-161.247190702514,-19.5553717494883,2.63210227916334));
#422=CARTESIAN_POINT('',(-161.331370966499,-19.5553717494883,2.62780900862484));
#423=CARTESIAN_POINT('',(-161.498898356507,-19.5553717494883,2.61069058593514));
#424=CARTESIAN_POINT('',(-161.582244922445,-19.5553717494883,2.5978600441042));
#425=CARTESIAN_POINT('',(-161.801164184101,-19.5553717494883,2.55261481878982));
#426=CARTESIAN_POINT('',(-161.935296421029,-19.5553717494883,2.51288252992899));
#427=CARTESIAN_POINT('',(-162.195079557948,-19.5553717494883,2.41143114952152));
#428=CARTESIAN_POINT('',(-162.320720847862,-19.5553717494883,2.3496876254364));
#429=CARTESIAN_POINT('',(-162.559809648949,-19.5553717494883,2.20600089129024));
#430=CARTESIAN_POINT('',(-162.673262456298,-19.5553717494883,2.12406650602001));
#431=CARTESIAN_POINT('',(-162.884770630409,-19.5553717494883,1.94233439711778));
#432=CARTESIAN_POINT('',(-162.98282968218,-19.5553717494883,1.84254096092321));
#433=CARTESIAN_POINT('',(-163.160814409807,-19.5553717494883,1.62789843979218));
#434=CARTESIAN_POINT('',(-163.240738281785,-19.5553717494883,1.51304785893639));
#435=CARTESIAN_POINT('',(-163.380172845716,-19.5553717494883,1.27155407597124));
#436=CARTESIAN_POINT('',(-163.439682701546,-19.5553717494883,1.14491039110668));
#437=CARTESIAN_POINT('',(-163.536594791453,-19.5553717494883,0.883432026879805));
#438=CARTESIAN_POINT('',(-163.57399744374,-19.5553717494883,0.748597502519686));
#439=CARTESIAN_POINT('',(-163.625634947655,-19.5553717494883,0.47456328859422));
#440=CARTESIAN_POINT('',(-163.639869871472,-19.5553717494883,0.335363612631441));
#441=CARTESIAN_POINT('',(-163.644768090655,-19.5553717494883,0.0565500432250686));
#442=CARTESIAN_POINT('',(-163.635431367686,-19.5553717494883,-0.0830638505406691));
#443=CARTESIAN_POINT('',(-163.593451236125,-19.5553717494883,-0.358742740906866));
#444=CARTESIAN_POINT('',(-163.560807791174,-19.5553717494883,-0.494807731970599));
#445=CARTESIAN_POINT('',(-163.473140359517,-19.5553717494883,-0.75952774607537));
#446=CARTESIAN_POINT('',(-163.41811609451,-19.5553717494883,-0.888182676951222));
#447=CARTESIAN_POINT('',(-163.287250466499,-19.5553717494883,-1.13442527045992));
#448=CARTESIAN_POINT('',(-163.211409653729,-19.5553717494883,-1.25201322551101));
#449=CARTESIAN_POINT('',(-163.041069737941,-19.5553717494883,-1.47278061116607));
#450=CARTESIAN_POINT('',(-162.946571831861,-19.5553717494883,-1.57596096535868));
#451=CARTESIAN_POINT('',(-162.741576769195,-19.5553717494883,-1.76500863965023));
#452=CARTESIAN_POINT('',(-162.631077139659,-19.5553717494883,-1.85087327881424));
#453=CARTESIAN_POINT('',(-162.397209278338,-19.5553717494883,-2.0028513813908));
#454=CARTESIAN_POINT('',(-162.273837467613,-19.5553717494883,-2.06895933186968));
#455=CARTESIAN_POINT('',(-162.017789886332,-19.5553717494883,-2.17947999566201));
#456=CARTESIAN_POINT('',(-161.885120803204,-19.5553717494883,-2.22390812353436));
#457=CARTESIAN_POINT('',(-161.653783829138,-19.5553717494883,-2.28025921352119));
#458=CARTESIAN_POINT('',(-161.55646039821,-19.5553717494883,-2.29787961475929));
#459=CARTESIAN_POINT('',(-161.360419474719,-19.5553717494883,-2.32139798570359));
#460=CARTESIAN_POINT('',(-161.261702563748,-19.5553717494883,-2.32730070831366));
#461=CARTESIAN_POINT('',(-161.163,-19.5553717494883,-2.32730155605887));
#462=B_SPLINE_CURVE_WITH_KNOTS('',3,(#380,#381,#382,#383,#384,#385,#386,#387,#388,#389,#390,
#391,#392,#393,#394,#395,#396,#397,#398,#399,#400,#401,#402,#403,#404,#405,#406,#407,#408,#409,
#410,#411,#412,#413,#414,#415,#416,#417,#418,#419,#420,#421,#422,#423,#424,#425,#426,#427,#428,
#429,#430,#431,#432,#433,#434,#435,#436,#437,#438,#439,#440,#441,#442,#443,#444,#445,#446,#447,
#448,#449,#450,#451,#452,#453,#454,#455,#456,#457,#458,#459,#460,#461),.UNSPECIFIED.,.T.,.F.,(4,
2,2,2,2,2,2,2,2,2,2,2,2,2,2,2,2,2,2,2,2,2,2,2,2,2,2,2,2,2,2,2,2,2,2,2,2,2,2,2,4),(0.,
0.252435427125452,0.505030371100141,0.922589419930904,1.34061341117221,1.75845502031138,
2.17619645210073,2.59397941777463,3.0117794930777,3.42957166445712,3.8473625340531,
4.26515372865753,4.6829455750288,5.10074261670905,5.5185286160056,5.93628782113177,
6.35411165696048,6.77205197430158,7.18969469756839,7.4857622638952,7.7817097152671,
8.03414514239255,8.28674008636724,8.704299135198,9.12232312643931,9.54016473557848,
9.95790616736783,10.3756891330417,10.7934892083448,11.2112813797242,11.6290722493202,
12.0468634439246,12.4646552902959,12.8824523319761,13.3002383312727,13.7179975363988,
14.1358213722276,14.5537616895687,14.9714044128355,15.2674719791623,15.5634194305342),.UNSPECIFIED.);
#463=CARTESIAN_POINT('',(-161.163,-19.5553717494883,-2.32730155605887));
#464=VERTEX_POINT('',#463);
#465=EDGE_CURVE('E51',#464,#464,#462,.T.);
#466=ORIENTED_EDGE('',*,*,#465,.F.);
#467=EDGE_LOOP('',(#466));
#468=FACE_BOUND('',#467,.T.);
#469=CARTESIAN_POINT('',(-142.113,-19.5553717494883,-2.32730155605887));
#470=CARTESIAN_POINT('',(-142.028809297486,-19.5553717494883,-2.32730227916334));
#471=CARTESIAN_POINT('',(-141.944629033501,-19.5553717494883,-2.32300900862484));
#472=CARTESIAN_POINT('',(-141.777101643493,-19.5553717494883,-2.30589058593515));
#473=CARTESIAN_POINT('',(-141.693755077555,-19.5553717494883,-2.2930600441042));
#474=CARTESIAN_POINT('',(-141.474835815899,-19.5553717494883,-2.24781481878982));
#475=CARTESIAN_POINT('',(-141.340703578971,-19.5553717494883,-2.20808252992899));
#476=CARTESIAN_POINT('',(-141.080920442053,-19.5553717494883,-2.10663114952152));
#477=CARTESIAN_POINT('',(-140.955279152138,-19.5553717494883,-2.04488762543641));
#478=CARTESIAN_POINT('',(-140.716190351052,-19.5553717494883,-1.90120089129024));
#479=CARTESIAN_POINT('',(-140.602737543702,-19.5553717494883,-1.81926650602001));
#480=CARTESIAN_POINT('',(-140.391229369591,-19.5553717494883,-1.63753439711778));
#481=CARTESIAN_POINT('',(-140.29317031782,-19.5553717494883,-1.53774096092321));
#482=CARTESIAN_POINT('',(-140.115185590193,-19.5553717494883,-1.32309843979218));
#483=CARTESIAN_POINT('',(-140.035261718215,-19.5553717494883,-1.20824785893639));
#484=CARTESIAN_POINT('',(-139.895827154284,-19.5553717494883,-0.966754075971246));
#485=CARTESIAN_POINT('',(-139.836317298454,-19.5553717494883,-0.840110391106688));
#486=CARTESIAN_POINT('',(-139.739405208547,-19.5553717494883,-0.578632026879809));
#487=CARTESIAN_POINT('',(-139.702002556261,-19.5553717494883,-0.443797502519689));
#488=CARTESIAN_POINT('',(-139.650365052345,-19.5553717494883,-0.169763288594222));
#489=CARTESIAN_POINT('',(-139.636130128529,-19.5553717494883,-0.0305636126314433));
#490=CARTESIAN_POINT('',(-139.631231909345,-19.5553717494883,0.24824995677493));
#491=CARTESIAN_POINT('',(-139.640568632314,-19.5553717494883,0.387863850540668));
#492=CARTESIAN_POINT('',(-139.682548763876,-19.5553717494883,0.663542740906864));
#493=CARTESIAN_POINT('',(-139.715192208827,-19.5553717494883,0.799607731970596));
#494=CARTESIAN_POINT('',(-139.802859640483,-19.5553717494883,1.06432774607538));
#495=CARTESIAN_POINT('',(-139.85788390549,-19.5553717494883,1.19298267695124));
#496=CARTESIAN_POINT('',(-139.988749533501,-19.5553717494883,1.43922527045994));
#497=CARTESIAN_POINT('',(-140.064590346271,-19.5553717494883,1.55681322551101));
#498=CARTESIAN_POINT('',(-140.234930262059,-19.5553717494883,1.77758061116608));
#499=CARTESIAN_POINT('',(-140.329428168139,-19.5553717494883,1.88076096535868));
#500=CARTESIAN_POINT('',(-140.534423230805,-19.5553717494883,2.06980863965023));
#501=CARTESIAN_POINT('',(-140.644922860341,-19.5553717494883,2.15567327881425));
#502=CARTESIAN_POINT('',(-140.878790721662,-19.5553717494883,2.30765138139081));
#503=CARTESIAN_POINT('',(-141.002162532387,-19.5553717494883,2.37375933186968));
#504=CARTESIAN_POINT('',(-141.258210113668,-19.5553717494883,2.484279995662));
#505=CARTESIAN_POINT('',(-141.390879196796,-19.5553717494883,2.52870812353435));
#506=CARTESIAN_POINT('',(-141.622216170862,-19.5553717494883,2.58505921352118));
#507=CARTESIAN_POINT('',(-141.71953960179,-19.5553717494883,2.60267961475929));
#508=CARTESIAN_POINT('',(-141.915580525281,-19.5553717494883,2.62619798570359));
#509=CARTESIAN_POINT('',(-142.014297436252,-19.5553717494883,2.63210070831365));
#510=CARTESIAN_POINT('',(-142.197190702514,-19.5553717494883,2.63210227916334));
#511=CARTESIAN_POINT('',(-142.281370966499,-19.5553717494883,2.62780900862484));
#512=CARTESIAN_POINT('',(-142.448898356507,-19.5553717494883,2.61069058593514));
#513=CARTESIAN_POINT('',(-142.532244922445,-19.5553717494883,2.5978600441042));
#514=CARTESIAN_POINT('',(-142.751164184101,-19.5553717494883,2.55261481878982));
#515=CARTESIAN_POINT('',(-142.885296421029,-19.5553717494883,2.51288252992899));
#516=CARTESIAN_POINT('',(-143.145079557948,-19.5553717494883,2.41143114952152));
#517=CARTESIAN_POINT('',(-143.270720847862,-19.5553717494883,2.3496876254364));
#518=CARTESIAN_POINT('',(-143.509809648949,-19.5553717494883,2.20600089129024));
#519=CARTESIAN_POINT('',(-143.623262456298,-19.5553717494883,2.12406650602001));
#520=CARTESIAN_POINT('',(-143.834770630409,-19.5553717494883,1.94233439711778));
#521=CARTESIAN_POINT('',(-143.93282968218,-19.5553717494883,1.84254096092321));
#522=CARTESIAN_POINT('',(-144.110814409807,-19.5553717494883,1.62789843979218));
#523=CARTESIAN_POINT('',(-144.190738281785,-19.5553717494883,1.51304785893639));
#524=CARTESIAN_POINT('',(-144.330172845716,-19.5553717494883,1.27155407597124));
#525=CARTESIAN_POINT('',(-144.389682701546,-19.5553717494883,1.14491039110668));
#526=CARTESIAN_POINT('',(-144.486594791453,-19.5553717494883,0.883432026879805));
#527=CARTESIAN_POINT('',(-144.52399744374,-19.5553717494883,0.748597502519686));
#528=CARTESIAN_POINT('',(-144.575634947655,-19.5553717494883,0.47456328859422));
#529=CARTESIAN_POINT('',(-144.589869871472,-19.5553717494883,0.335363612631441));
#530=CARTESIAN_POINT('',(-144.594768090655,-19.5553717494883,0.0565500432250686));
#531=CARTESIAN_POINT('',(-144.585431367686,-19.5553717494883,-0.0830638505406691));
#532=CARTESIAN_POINT('',(-144.543451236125,-19.5553717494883,-0.358742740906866));
#533=CARTESIAN_POINT('',(-144.510807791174,-19.5553717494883,-0.494807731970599));
#534=CARTESIAN_POINT('',(-144.423140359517,-19.5553717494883,-0.75952774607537));
#535=CARTESIAN_POINT('',(-144.36811609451,-19.5553717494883,-0.888182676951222));
#536=CARTESIAN_POINT('',(-144.237250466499,-19.5553717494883,-1.13442527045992));
#537=CARTESIAN_POINT('',(-144.161409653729,-19.5553717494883,-1.25201322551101));
#538=CARTESIAN_POINT('',(-143.991069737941,-19.5553717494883,-1.47278061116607));
#539=CARTESIAN_POINT('',(-143.896571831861,-19.5553717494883,-1.57596096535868));
#540=CARTESIAN_POINT('',(-143.691576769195,-19.5553717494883,-1.76500863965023));
#541=CARTESIAN_POINT('',(-143.581077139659,-19.5553717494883,-1.85087327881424));
#542=CARTESIAN_POINT('',(-143.347209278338,-19.5553717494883,-2.0028513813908));
#543=CARTESIAN_POINT('',(-143.223837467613,-19.5553717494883,-2.06895933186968));
#544=CARTESIAN_POINT('',(-142.967789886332,-19.5553717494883,-2.17947999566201));
#545=CARTESIAN_POINT('',(-142.835120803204,-19.5553717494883,-2.22390812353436));
#546=CARTESIAN_POINT('',(-142.603783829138,-19.5553717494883,-2.28025921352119));
#547=CARTESIAN_POINT('',(-142.50646039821,-19.5553717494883,-2.29787961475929));
#548=CARTESIAN_POINT('',(-142.310419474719,-19.5553717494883,-2.32139798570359));
#549=CARTESIAN_POINT('',(-142.211702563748,-19.5553717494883,-2.32730070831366));
#550=CARTESIAN_POINT('',(-142.113,-19.5553717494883,-2.32730155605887));
#551=B_SPLINE_CURVE_WITH_KNOTS('',3,(#469,#470,#471,#472,#473,#474,#475,#476,#477,#478,#479,
#480,#481,#482,#483,#484,#485,#486,#487,#488,#489,#490,#491,#492,#493,#494,#495,#496,#497,#498,
#499,#500,#501,#502,#503,#504,#505,#506,#507,#508,#509,#510,#511,#512,#513,#514,#515,#516,#517,
#518,#519,#520,#521,#522,#523,#524,#525,#526,#527,#528,#529,#530,#531,#532,#533,#534,#535,#536,
#537,#538,#539,#540,#541,#542,#543,#544,#545,#546,#547,#548,#549,#550),.UNSPECIFIED.,.T.,.F.,(4,
2,2,2,2,2,2,2,2,2,2,2,2,2,2,2,2,2,2,2,2,2,2,2,2,2,2,2,2,2,2,2,2,2,2,2,2,2,2,2,4),(0.,
0.252435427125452,0.505030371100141,0.922589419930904,1.34061341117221,1.75845502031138,
2.17619645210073,2.59397941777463,3.0117794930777,3.42957166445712,3.8473625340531,
4.26515372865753,4.6829455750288,5.10074261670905,5.5185286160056,5.93628782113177,
6.35411165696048,6.77205197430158,7.18969469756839,7.4857622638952,7.7817097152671,
8.03414514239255,8.28674008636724,8.704299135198,9.12232312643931,9.54016473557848,
9.95790616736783,10.3756891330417,10.7934892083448,11.2112813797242,11.6290722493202,
12.0468634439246,12.4646552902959,12.8824523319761,13.3002383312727,13.7179975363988,
14.1358213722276,14.5537616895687,14.9714044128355,15.2674719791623,15.5634194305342),.UNSPECIFIED.);
#552=CARTESIAN_POINT('',(-142.113,-19.5553717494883,-2.32730155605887));
#553=VERTEX_POINT('',#552);
#554=EDGE_CURVE('E283',#553,#553,#551,.T.);
#555=ORIENTED_EDGE('',*,*,#554,.F.);
#556=EDGE_LOOP('',(#555));
#557=FACE_BOUND('',#556,.T.);
#558=DIRECTION('',(0.,0.,1.));
#559=VECTOR('',#558,1.);
#560=CARTESIAN_POINT('',(-243.713,-19.5553717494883,3.9624));
#561=LINE('',#560,#559);
#562=CARTESIAN_POINT('',(-243.713,-19.5553717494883,-3.6576));
#563=VERTEX_POINT('',#562);
#564=CARTESIAN_POINT('',(-243.713,-19.5553717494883,3.9624));
#565=VERTEX_POINT('',#564);
#566=EDGE_CURVE('E116',#563,#565,#561,.T.);
#567=ORIENTED_EDGE('',*,*,#566,.F.);
#568=DIRECTION('',(-1.,0.,0.));
#569=VECTOR('',#568,1.);
#570=CARTESIAN_POINT('',(-243.713,-19.5553717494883,-3.6576));
#571=LINE('',#570,#569);
#572=CARTESIAN_POINT('',(-135.763,-19.5553717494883,-3.6576));
#573=VERTEX_POINT('',#572);
#574=EDGE_CURVE('E106',#573,#563,#571,.T.);
#575=ORIENTED_EDGE('',*,*,#574,.F.);
#576=DIRECTION('',(0.,0.,-1.));
#577=VECTOR('',#576,1.);
#578=CARTESIAN_POINT('',(-135.763,-19.5553717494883,-2.32730155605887));
#579=LINE('',#578,#577);
#580=CARTESIAN_POINT('',(-135.763,-19.5553717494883,3.96240000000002));
#581=VERTEX_POINT('',#580);
#582=EDGE_CURVE('E77',#581,#573,#579,.T.);
#583=ORIENTED_EDGE('',*,*,#582,.F.);
#584=DIRECTION('',(1.,0.,0.));
#585=VECTOR('',#584,1.);
#586=CARTESIAN_POINT('',(-135.763,-19.5553717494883,3.96240000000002));
#587=LINE('',#586,#585);
#588=EDGE_CURVE('E124',#565,#581,#587,.T.);
#589=ORIENTED_EDGE('',*,*,#588,.F.);
#590=EDGE_LOOP('',(#567,#575,#583,#589));
#591=FACE_BOUND('',#590,.T.);
#592=ADVANCED_FACE('F45',(#112,#201,#290,#379,#468,#557,#591),#23,.F.);
#593=CARTESIAN_POINT('',(-243.713,-18.7933717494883,3.9624));
#594=DIRECTION('',(0.,-1.,0.));
#595=DIRECTION('',(0.,0.,-1.));
#596=AXIS2_PLACEMENT_3D('',#593,#594,#595);
#597=PLANE('',#596);
#598=CARTESIAN_POINT('',(-142.113,-18.7933717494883,2.63210155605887));
#599=CARTESIAN_POINT('',(-142.028809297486,-18.7933717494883,2.63210227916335));
#600=CARTESIAN_POINT('',(-141.944629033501,-18.7933717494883,2.62780900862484));
#601=CARTESIAN_POINT('',(-141.777101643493,-18.7933717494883,2.61069058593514));
#602=CARTESIAN_POINT('',(-141.693755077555,-18.7933717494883,2.5978600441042));
#603=CARTESIAN_POINT('',(-141.474835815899,-18.7933717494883,2.55261481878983));
#604=CARTESIAN_POINT('',(-141.340703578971,-18.7933717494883,2.51288252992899));
#605=CARTESIAN_POINT('',(-141.080920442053,-18.7933717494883,2.41143114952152));
#606=CARTESIAN_POINT('',(-140.955279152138,-18.7933717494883,2.3496876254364));
#607=CARTESIAN_POINT('',(-140.716190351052,-18.7933717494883,2.20600089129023));
#608=CARTESIAN_POINT('',(-140.602737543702,-18.7933717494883,2.12406650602));
#609=CARTESIAN_POINT('',(-140.391229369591,-18.7933717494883,1.94233439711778));
#610=CARTESIAN_POINT('',(-140.29317031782,-18.7933717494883,1.84254096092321));
#611=CARTESIAN_POINT('',(-140.115185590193,-18.7933717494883,1.62789843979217));
#612=CARTESIAN_POINT('',(-140.035261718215,-18.7933717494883,1.51304785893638));
#613=CARTESIAN_POINT('',(-139.895827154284,-18.7933717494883,1.27155407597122));
#614=CARTESIAN_POINT('',(-139.836317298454,-18.7933717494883,1.14491039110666));
#615=CARTESIAN_POINT('',(-139.739405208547,-18.7933717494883,0.883432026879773));
#616=CARTESIAN_POINT('',(-139.702002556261,-18.7933717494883,0.748597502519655));
#617=CARTESIAN_POINT('',(-139.650365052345,-18.7933717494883,0.474563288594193));
#618=CARTESIAN_POINT('',(-139.636130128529,-18.7933717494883,0.335363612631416));
#619=CARTESIAN_POINT('',(-139.631231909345,-18.7933717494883,0.0565500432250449));
#620=CARTESIAN_POINT('',(-139.640568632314,-18.7933717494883,-0.0830638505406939));
#621=CARTESIAN_POINT('',(-139.682548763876,-18.7933717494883,-0.358742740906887));
#622=CARTESIAN_POINT('',(-139.715192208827,-18.7933717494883,-0.494807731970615));
#623=CARTESIAN_POINT('',(-139.802859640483,-18.7933717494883,-0.759527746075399));
#624=CARTESIAN_POINT('',(-139.85788390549,-18.7933717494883,-0.888182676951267));
#625=CARTESIAN_POINT('',(-139.988749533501,-18.7933717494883,-1.13442527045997));
#626=CARTESIAN_POINT('',(-140.064590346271,-18.7933717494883,-1.25201322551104));
#627=CARTESIAN_POINT('',(-140.234930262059,-18.7933717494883,-1.47278061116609));
#628=CARTESIAN_POINT('',(-140.329428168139,-18.7933717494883,-1.5759609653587));
#629=CARTESIAN_POINT('',(-140.534423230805,-18.7933717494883,-1.76500863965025));
#630=CARTESIAN_POINT('',(-140.644922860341,-18.7933717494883,-1.85087327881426));
#631=CARTESIAN_POINT('',(-140.878790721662,-18.7933717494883,-2.00285138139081));
#632=CARTESIAN_POINT('',(-141.002162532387,-18.7933717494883,-2.06895933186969));
#633=CARTESIAN_POINT('',(-141.258210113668,-18.7933717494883,-2.17947999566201));
#634=CARTESIAN_POINT('',(-141.390879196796,-18.7933717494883,-2.22390812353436));
#635=CARTESIAN_POINT('',(-141.622216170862,-18.7933717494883,-2.28025921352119));
#636=CARTESIAN_POINT('',(-141.71953960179,-18.7933717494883,-2.29787961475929));
#637=CARTESIAN_POINT('',(-141.915580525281,-18.7933717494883,-2.32139798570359));
#638=CARTESIAN_POINT('',(-142.014297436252,-18.7933717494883,-2.32730070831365));
#639=CARTESIAN_POINT('',(-142.197190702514,-18.7933717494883,-2.32730227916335));
#640=CARTESIAN_POINT('',(-142.281370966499,-18.7933717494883,-2.32300900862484));
#641=CARTESIAN_POINT('',(-142.448898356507,-18.7933717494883,-2.30589058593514));
#642=CARTESIAN_POINT('',(-142.532244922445,-18.7933717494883,-2.2930600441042));
#643=CARTESIAN_POINT('',(-142.751164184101,-18.7933717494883,-2.24781481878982));
#644=CARTESIAN_POINT('',(-142.885296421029,-18.7933717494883,-2.20808252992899));
#645=CARTESIAN_POINT('',(-143.145079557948,-18.7933717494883,-2.10663114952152));
#646=CARTESIAN_POINT('',(-143.270720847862,-18.7933717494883,-2.0448876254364));
#647=CARTESIAN_POINT('',(-143.509809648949,-18.7933717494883,-1.90120089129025));
#648=CARTESIAN_POINT('',(-143.623262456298,-18.7933717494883,-1.81926650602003));
#649=CARTESIAN_POINT('',(-143.834770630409,-18.7933717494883,-1.6375343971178));
#650=CARTESIAN_POINT('',(-143.93282968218,-18.7933717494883,-1.53774096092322));
#651=CARTESIAN_POINT('',(-144.110814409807,-18.7933717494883,-1.32309843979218));
#652=CARTESIAN_POINT('',(-144.190738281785,-18.7933717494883,-1.20824785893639));
#653=CARTESIAN_POINT('',(-144.330172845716,-18.7933717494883,-0.966754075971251));
#654=CARTESIAN_POINT('',(-144.389682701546,-18.7933717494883,-0.840110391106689));
#655=CARTESIAN_POINT('',(-144.486594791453,-18.7933717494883,-0.578632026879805));
#656=CARTESIAN_POINT('',(-144.52399744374,-18.7933717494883,-0.443797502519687));
#657=CARTESIAN_POINT('',(-144.575634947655,-18.7933717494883,-0.16976328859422));
#658=CARTESIAN_POINT('',(-144.589869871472,-18.7933717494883,-0.0305636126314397));
#659=CARTESIAN_POINT('',(-144.594768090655,-18.7933717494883,0.248249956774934));
#660=CARTESIAN_POINT('',(-144.585431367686,-18.7933717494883,0.387863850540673));
#661=CARTESIAN_POINT('',(-144.543451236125,-18.7933717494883,0.663542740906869));
#662=CARTESIAN_POINT('',(-144.510807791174,-18.7933717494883,0.7996077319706));
#663=CARTESIAN_POINT('',(-144.423140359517,-18.7933717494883,1.06432774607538));
#664=CARTESIAN_POINT('',(-144.36811609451,-18.7933717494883,1.19298267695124));
#665=CARTESIAN_POINT('',(-144.237250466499,-18.7933717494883,1.43922527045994));
#666=CARTESIAN_POINT('',(-144.161409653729,-18.7933717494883,1.55681322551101));
#667=CARTESIAN_POINT('',(-143.991069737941,-18.7933717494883,1.77758061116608));
#668=CARTESIAN_POINT('',(-143.896571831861,-18.7933717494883,1.88076096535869));
#669=CARTESIAN_POINT('',(-143.691576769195,-18.7933717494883,2.06980863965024));
#670=CARTESIAN_POINT('',(-143.581077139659,-18.7933717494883,2.15567327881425));
#671=CARTESIAN_POINT('',(-143.347209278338,-18.7933717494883,2.30765138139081));
#672=CARTESIAN_POINT('',(-143.223837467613,-18.7933717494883,2.37375933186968));
#673=CARTESIAN_POINT('',(-142.967789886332,-18.7933717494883,2.48427999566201));
#674=CARTESIAN_POINT('',(-142.835120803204,-18.7933717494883,2.52870812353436));
#675=CARTESIAN_POINT('',(-142.603783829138,-18.7933717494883,2.58505921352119));
#676=CARTESIAN_POINT('',(-142.50646039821,-18.7933717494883,2.60267961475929));
#677=CARTESIAN_POINT('',(-142.310419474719,-18.7933717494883,2.62619798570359));
#678=CARTESIAN_POINT('',(-142.211702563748,-18.7933717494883,2.63210070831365));
#679=CARTESIAN_POINT('',(-142.113,-18.7933717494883,2.63210155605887));
#680=B_SPLINE_CURVE_WITH_KNOTS('',3,(#598,#599,#600,#601,#602,#603,#604,#605,#606,#607,#608,
#609,#610,#611,#612,#613,#614,#615,#616,#617,#618,#619,#620,#621,#622,#623,#624,#625,#626,#627,
#628,#629,#630,#631,#632,#633,#634,#635,#636,#637,#638,#639,#640,#641,#642,#643,#644,#645,#646,
#647,#648,#649,#650,#651,#652,#653,#654,#655,#656,#657,#658,#659,#660,#661,#662,#663,#664,#665,
#666,#667,#668,#669,#670,#671,#672,#673,#674,#675,#676,#677,#678,#679),.UNSPECIFIED.,.T.,.F.,(4,
2,2,2,2,2,2,2,2,2,2,2,2,2,2,2,2,2,2,2,2,2,2,2,2,2,2,2,2,2,2,2,2,2,2,2,2,2,2,2,4),(0.,
0.252435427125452,0.505030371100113,0.922589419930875,1.34061341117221,1.75845502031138,
2.17619645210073,2.59397941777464,3.01177949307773,3.42957166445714,3.84736253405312,
4.26515372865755,4.68294557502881,5.10074261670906,5.5185286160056,5.93628782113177,
6.3541116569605,6.7720519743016,7.1896946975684,7.48576226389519,7.78170971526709,
8.03414514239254,8.28674008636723,8.70429913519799,9.1223231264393,9.54016473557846,
9.9579061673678,10.3756891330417,10.7934892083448,11.2112813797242,11.6290722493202,
12.0468634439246,12.4646552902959,12.8824523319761,13.3002383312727,13.7179975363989,
14.1358213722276,14.5537616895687,14.9714044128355,15.2674719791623,15.5634194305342),.UNSPECIFIED.);
#681=CARTESIAN_POINT('',(-142.113,-18.7933717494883,2.63210155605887));
#682=VERTEX_POINT('',#681);
#683=EDGE_CURVE('E12',#682,#682,#680,.T.);
#684=ORIENTED_EDGE('',*,*,#683,.F.);
#685=EDGE_LOOP('',(#684));
#686=FACE_BOUND('',#685,.T.);
#687=CARTESIAN_POINT('',(-161.163,-18.7933717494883,2.63210155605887));
#688=CARTESIAN_POINT('',(-161.078809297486,-18.7933717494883,2.63210227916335));
#689=CARTESIAN_POINT('',(-160.994629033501,-18.7933717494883,2.62780900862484));
#690=CARTESIAN_POINT('',(-160.827101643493,-18.7933717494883,2.61069058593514));
#691=CARTESIAN_POINT('',(-160.743755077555,-18.7933717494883,2.5978600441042));
#692=CARTESIAN_POINT('',(-160.524835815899,-18.7933717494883,2.55261481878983));
#693=CARTESIAN_POINT('',(-160.390703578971,-18.7933717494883,2.51288252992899));
#694=CARTESIAN_POINT('',(-160.130920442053,-18.7933717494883,2.41143114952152));
#695=CARTESIAN_POINT('',(-160.005279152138,-18.7933717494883,2.3496876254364));
#696=CARTESIAN_POINT('',(-159.766190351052,-18.7933717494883,2.20600089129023));
#697=CARTESIAN_POINT('',(-159.652737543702,-18.7933717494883,2.12406650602));
#698=CARTESIAN_POINT('',(-159.441229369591,-18.7933717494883,1.94233439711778));
#699=CARTESIAN_POINT('',(-159.34317031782,-18.7933717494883,1.84254096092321));
#700=CARTESIAN_POINT('',(-159.165185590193,-18.7933717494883,1.62789843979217));
#701=CARTESIAN_POINT('',(-159.085261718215,-18.7933717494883,1.51304785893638));
#702=CARTESIAN_POINT('',(-158.945827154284,-18.7933717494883,1.27155407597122));
#703=CARTESIAN_POINT('',(-158.886317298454,-18.7933717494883,1.14491039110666));
#704=CARTESIAN_POINT('',(-158.789405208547,-18.7933717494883,0.883432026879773));
#705=CARTESIAN_POINT('',(-158.752002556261,-18.7933717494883,0.748597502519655));
#706=CARTESIAN_POINT('',(-158.700365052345,-18.7933717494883,0.474563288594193));
#707=CARTESIAN_POINT('',(-158.686130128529,-18.7933717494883,0.335363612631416));
#708=CARTESIAN_POINT('',(-158.681231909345,-18.7933717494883,0.0565500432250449));
#709=CARTESIAN_POINT('',(-158.690568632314,-18.7933717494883,-0.0830638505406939));
#710=CARTESIAN_POINT('',(-158.732548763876,-18.7933717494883,-0.358742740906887));
#711=CARTESIAN_POINT('',(-158.765192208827,-18.7933717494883,-0.494807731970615));
#712=CARTESIAN_POINT('',(-158.852859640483,-18.7933717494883,-0.759527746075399));
#713=CARTESIAN_POINT('',(-158.90788390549,-18.7933717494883,-0.888182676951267));
#714=CARTESIAN_POINT('',(-159.038749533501,-18.7933717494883,-1.13442527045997));
#715=CARTESIAN_POINT('',(-159.114590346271,-18.7933717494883,-1.25201322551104));
#716=CARTESIAN_POINT('',(-159.284930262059,-18.7933717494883,-1.47278061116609));
#717=CARTESIAN_POINT('',(-159.379428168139,-18.7933717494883,-1.5759609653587));
#718=CARTESIAN_POINT('',(-159.584423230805,-18.7933717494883,-1.76500863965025));
#719=CARTESIAN_POINT('',(-159.694922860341,-18.7933717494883,-1.85087327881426));
#720=CARTESIAN_POINT('',(-159.928790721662,-18.7933717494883,-2.00285138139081));
#721=CARTESIAN_POINT('',(-160.052162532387,-18.7933717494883,-2.06895933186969));
#722=CARTESIAN_POINT('',(-160.308210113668,-18.7933717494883,-2.17947999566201));
#723=CARTESIAN_POINT('',(-160.440879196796,-18.7933717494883,-2.22390812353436));
#724=CARTESIAN_POINT('',(-160.672216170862,-18.7933717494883,-2.28025921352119));
#725=CARTESIAN_POINT('',(-160.76953960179,-18.7933717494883,-2.29787961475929));
#726=CARTESIAN_POINT('',(-160.965580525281,-18.7933717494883,-2.32139798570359));
#727=CARTESIAN_POINT('',(-161.064297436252,-18.7933717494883,-2.32730070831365));
#728=CARTESIAN_POINT('',(-161.247190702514,-18.7933717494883,-2.32730227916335));
#729=CARTESIAN_POINT('',(-161.331370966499,-18.7933717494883,-2.32300900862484));
#730=CARTESIAN_POINT('',(-161.498898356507,-18.7933717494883,-2.30589058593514));
#731=CARTESIAN_POINT('',(-161.582244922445,-18.7933717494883,-2.2930600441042));
#732=CARTESIAN_POINT('',(-161.801164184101,-18.7933717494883,-2.24781481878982));
#733=CARTESIAN_POINT('',(-161.935296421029,-18.7933717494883,-2.20808252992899));
#734=CARTESIAN_POINT('',(-162.195079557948,-18.7933717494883,-2.10663114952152));
#735=CARTESIAN_POINT('',(-162.320720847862,-18.7933717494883,-2.0448876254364));
#736=CARTESIAN_POINT('',(-162.559809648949,-18.7933717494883,-1.90120089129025));
#737=CARTESIAN_POINT('',(-162.673262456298,-18.7933717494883,-1.81926650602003));
#738=CARTESIAN_POINT('',(-162.884770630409,-18.7933717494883,-1.6375343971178));
#739=CARTESIAN_POINT('',(-162.98282968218,-18.7933717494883,-1.53774096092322));
#740=CARTESIAN_POINT('',(-163.160814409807,-18.7933717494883,-1.32309843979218));
#741=CARTESIAN_POINT('',(-163.240738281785,-18.7933717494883,-1.20824785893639));
#742=CARTESIAN_POINT('',(-163.380172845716,-18.7933717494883,-0.966754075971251));
#743=CARTESIAN_POINT('',(-163.439682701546,-18.7933717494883,-0.840110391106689));
#744=CARTESIAN_POINT('',(-163.536594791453,-18.7933717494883,-0.578632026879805));
#745=CARTESIAN_POINT('',(-163.57399744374,-18.7933717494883,-0.443797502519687));
#746=CARTESIAN_POINT('',(-163.625634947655,-18.7933717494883,-0.16976328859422));
#747=CARTESIAN_POINT('',(-163.639869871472,-18.7933717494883,-0.0305636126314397));
#748=CARTESIAN_POINT('',(-163.644768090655,-18.7933717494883,0.248249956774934));
#749=CARTESIAN_POINT('',(-163.635431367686,-18.7933717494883,0.387863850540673));
#750=CARTESIAN_POINT('',(-163.593451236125,-18.7933717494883,0.663542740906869));
#751=CARTESIAN_POINT('',(-163.560807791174,-18.7933717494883,0.7996077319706));
#752=CARTESIAN_POINT('',(-163.473140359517,-18.7933717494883,1.06432774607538));
#753=CARTESIAN_POINT('',(-163.41811609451,-18.7933717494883,1.19298267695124));
#754=CARTESIAN_POINT('',(-163.287250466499,-18.7933717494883,1.43922527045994));
#755=CARTESIAN_POINT('',(-163.211409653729,-18.7933717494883,1.55681322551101));
#756=CARTESIAN_POINT('',(-163.041069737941,-18.7933717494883,1.77758061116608));
#757=CARTESIAN_POINT('',(-162.946571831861,-18.7933717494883,1.88076096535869));
#758=CARTESIAN_POINT('',(-162.741576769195,-18.7933717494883,2.06980863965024));
#759=CARTESIAN_POINT('',(-162.631077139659,-18.7933717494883,2.15567327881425));
#760=CARTESIAN_POINT('',(-162.397209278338,-18.7933717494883,2.30765138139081));
#761=CARTESIAN_POINT('',(-162.273837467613,-18.7933717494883,2.37375933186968));
#762=CARTESIAN_POINT('',(-162.017789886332,-18.7933717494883,2.48427999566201));
#763=CARTESIAN_POINT('',(-161.885120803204,-18.7933717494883,2.52870812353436));
#764=CARTESIAN_POINT('',(-161.653783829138,-18.7933717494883,2.58505921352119));
#765=CARTESIAN_POINT('',(-161.55646039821,-18.7933717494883,2.60267961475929));
#766=CARTESIAN_POINT('',(-161.360419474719,-18.7933717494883,2.62619798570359));
#767=CARTESIAN_POINT('',(-161.261702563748,-18.7933717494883,2.63210070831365));
#768=CARTESIAN_POINT('',(-161.163,-18.7933717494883,2.63210155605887));
#769=B_SPLINE_CURVE_WITH_KNOTS('',3,(#687,#688,#689,#690,#691,#692,#693,#694,#695,#696,#697,
#698,#699,#700,#701,#702,#703,#704,#705,#706,#707,#708,#709,#710,#711,#712,#713,#714,#715,#716,
#717,#718,#719,#720,#721,#722,#723,#724,#725,#726,#727,#728,#729,#730,#731,#732,#733,#734,#735,
#736,#737,#738,#739,#740,#741,#742,#743,#744,#745,#746,#747,#748,#749,#750,#751,#752,#753,#754,
#755,#756,#757,#758,#759,#760,#761,#762,#763,#764,#765,#766,#767,#768),.UNSPECIFIED.,.T.,.F.,(4,
2,2,2,2,2,2,2,2,2,2,2,2,2,2,2,2,2,2,2,2,2,2,2,2,2,2,2,2,2,2,2,2,2,2,2,2,2,2,2,4),(0.,
0.252435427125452,0.505030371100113,0.922589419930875,1.34061341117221,1.75845502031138,
2.17619645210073,2.59397941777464,3.01177949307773,3.42957166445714,3.84736253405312,
4.26515372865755,4.68294557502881,5.10074261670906,5.5185286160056,5.93628782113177,
6.3541116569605,6.7720519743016,7.1896946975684,7.48576226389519,7.78170971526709,
8.03414514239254,8.28674008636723,8.70429913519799,9.1223231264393,9.54016473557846,
9.9579061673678,10.3756891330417,10.7934892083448,11.2112813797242,11.6290722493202,
12.0468634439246,12.4646552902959,12.8824523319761,13.3002383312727,13.7179975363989,
14.1358213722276,14.5537616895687,14.9714044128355,15.2674719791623,15.5634194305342),.UNSPECIFIED.);
#770=CARTESIAN_POINT('',(-161.163,-18.7933717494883,2.63210155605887));
#771=VERTEX_POINT('',#770);
#772=EDGE_CURVE('E338',#771,#771,#769,.T.);
#773=ORIENTED_EDGE('',*,*,#772,.F.);
#774=EDGE_LOOP('',(#773));
#775=FACE_BOUND('',#774,.T.);
#776=CARTESIAN_POINT('',(-180.213,-18.7933717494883,2.63210155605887));
#777=CARTESIAN_POINT('',(-180.128809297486,-18.7933717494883,2.63210227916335));
#778=CARTESIAN_POINT('',(-180.044629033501,-18.7933717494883,2.62780900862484));
#779=CARTESIAN_POINT('',(-179.877101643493,-18.7933717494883,2.61069058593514));
#780=CARTESIAN_POINT('',(-179.793755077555,-18.7933717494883,2.5978600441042));
#781=CARTESIAN_POINT('',(-179.574835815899,-18.7933717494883,2.55261481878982));
#782=CARTESIAN_POINT('',(-179.440703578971,-18.7933717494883,2.51288252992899));
#783=CARTESIAN_POINT('',(-179.180920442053,-18.7933717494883,2.41143114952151));
#784=CARTESIAN_POINT('',(-179.055279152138,-18.7933717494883,2.34968762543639));
#785=CARTESIAN_POINT('',(-178.816190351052,-18.7933717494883,2.20600089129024));
#786=CARTESIAN_POINT('',(-178.702737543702,-18.7933717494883,2.12406650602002));
#787=CARTESIAN_POINT('',(-178.491229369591,-18.7933717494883,1.9423343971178));
#788=CARTESIAN_POINT('',(-178.39317031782,-18.7933717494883,1.84254096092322));
#789=CARTESIAN_POINT('',(-178.215185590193,-18.7933717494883,1.62789843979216));
#790=CARTESIAN_POINT('',(-178.135261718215,-18.7933717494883,1.51304785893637));
#791=CARTESIAN_POINT('',(-177.995827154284,-18.7933717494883,1.27155407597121));
#792=CARTESIAN_POINT('',(-177.936317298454,-18.7933717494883,1.14491039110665));
#793=CARTESIAN_POINT('',(-177.839405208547,-18.7933717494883,0.883432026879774));
#794=CARTESIAN_POINT('',(-177.802002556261,-18.7933717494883,0.748597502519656));
#795=CARTESIAN_POINT('',(-177.750365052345,-18.7933717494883,0.474563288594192));
#796=CARTESIAN_POINT('',(-177.736130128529,-18.7933717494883,0.335363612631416));
#797=CARTESIAN_POINT('',(-177.731231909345,-18.7933717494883,0.0565500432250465));
#798=CARTESIAN_POINT('',(-177.740568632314,-18.7933717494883,-0.0830638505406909));
#799=CARTESIAN_POINT('',(-177.782548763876,-18.7933717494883,-0.358742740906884));
#800=CARTESIAN_POINT('',(-177.815192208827,-18.7933717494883,-0.494807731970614));
#801=CARTESIAN_POINT('',(-177.902859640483,-18.7933717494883,-0.759527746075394));
#802=CARTESIAN_POINT('',(-177.95788390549,-18.7933717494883,-0.888182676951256));
#803=CARTESIAN_POINT('',(-178.088749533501,-18.7933717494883,-1.13442527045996));
#804=CARTESIAN_POINT('',(-178.164590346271,-18.7933717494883,-1.25201322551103));
#805=CARTESIAN_POINT('',(-178.334930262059,-18.7933717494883,-1.47278061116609));
#806=CARTESIAN_POINT('',(-178.429428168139,-18.7933717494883,-1.5759609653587));
#807=CARTESIAN_POINT('',(-178.634423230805,-18.7933717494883,-1.76500863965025));
#808=CARTESIAN_POINT('',(-178.744922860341,-18.7933717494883,-1.85087327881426));
#809=CARTESIAN_POINT('',(-178.978790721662,-18.7933717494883,-2.00285138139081));
#810=CARTESIAN_POINT('',(-179.102162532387,-18.7933717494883,-2.06895933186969));
#811=CARTESIAN_POINT('',(-179.358210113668,-18.7933717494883,-2.17947999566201));
#812=CARTESIAN_POINT('',(-179.490879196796,-18.7933717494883,-2.22390812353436));
#813=CARTESIAN_POINT('',(-179.722216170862,-18.7933717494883,-2.28025921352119));
#814=CARTESIAN_POINT('',(-179.81953960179,-18.7933717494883,-2.29787961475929));
#815=CARTESIAN_POINT('',(-180.015580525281,-18.7933717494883,-2.32139798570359));
#816=CARTESIAN_POINT('',(-180.114297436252,-18.7933717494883,-2.32730070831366));
#817=CARTESIAN_POINT('',(-180.297190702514,-18.7933717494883,-2.32730227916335));
#818=CARTESIAN_POINT('',(-180.381370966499,-18.7933717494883,-2.32300900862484));
#819=CARTESIAN_POINT('',(-180.548898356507,-18.7933717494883,-2.30589058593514));
#820=CARTESIAN_POINT('',(-180.632244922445,-18.7933717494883,-2.2930600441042));
#821=CARTESIAN_POINT('',(-180.851164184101,-18.7933717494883,-2.24781481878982));
#822=CARTESIAN_POINT('',(-180.985296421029,-18.7933717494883,-2.20808252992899));
#823=CARTESIAN_POINT('',(-181.245079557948,-18.7933717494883,-2.10663114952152));
#824=CARTESIAN_POINT('',(-181.370720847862,-18.7933717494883,-2.0448876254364));
#825=CARTESIAN_POINT('',(-181.609809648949,-18.7933717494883,-1.90120089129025));
#826=CARTESIAN_POINT('',(-181.723262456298,-18.7933717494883,-1.81926650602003));
#827=CARTESIAN_POINT('',(-181.934770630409,-18.7933717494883,-1.6375343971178));
#828=CARTESIAN_POINT('',(-182.03282968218,-18.7933717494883,-1.53774096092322));
#829=CARTESIAN_POINT('',(-182.210814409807,-18.7933717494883,-1.32309843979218));
#830=CARTESIAN_POINT('',(-182.290738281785,-18.7933717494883,-1.20824785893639));
#831=CARTESIAN_POINT('',(-182.430172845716,-18.7933717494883,-0.966754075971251));
#832=CARTESIAN_POINT('',(-182.489682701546,-18.7933717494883,-0.840110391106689));
#833=CARTESIAN_POINT('',(-182.586594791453,-18.7933717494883,-0.578632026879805));
#834=CARTESIAN_POINT('',(-182.62399744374,-18.7933717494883,-0.443797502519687));
#835=CARTESIAN_POINT('',(-182.675634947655,-18.7933717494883,-0.16976328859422));
#836=CARTESIAN_POINT('',(-182.689869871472,-18.7933717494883,-0.0305636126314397));
#837=CARTESIAN_POINT('',(-182.694768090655,-18.7933717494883,0.248249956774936));
#838=CARTESIAN_POINT('',(-182.685431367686,-18.7933717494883,0.387863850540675));
#839=CARTESIAN_POINT('',(-182.643451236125,-18.7933717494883,0.663542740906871));
#840=CARTESIAN_POINT('',(-182.610807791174,-18.7933717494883,0.799607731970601));
#841=CARTESIAN_POINT('',(-182.523140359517,-18.7933717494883,1.06432774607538));
#842=CARTESIAN_POINT('',(-182.46811609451,-18.7933717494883,1.19298267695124));
#843=CARTESIAN_POINT('',(-182.337250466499,-18.7933717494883,1.43922527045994));
#844=CARTESIAN_POINT('',(-182.261409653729,-18.7933717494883,1.55681322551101));
#845=CARTESIAN_POINT('',(-182.091069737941,-18.7933717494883,1.77758061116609));
#846=CARTESIAN_POINT('',(-181.996571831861,-18.7933717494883,1.88076096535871));
#847=CARTESIAN_POINT('',(-181.791576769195,-18.7933717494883,2.06980863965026));
#848=CARTESIAN_POINT('',(-181.681077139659,-18.7933717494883,2.15567327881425));
#849=CARTESIAN_POINT('',(-181.447209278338,-18.7933717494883,2.30765138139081));
#850=CARTESIAN_POINT('',(-181.323837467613,-18.7933717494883,2.37375933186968));
#851=CARTESIAN_POINT('',(-181.067789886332,-18.7933717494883,2.48427999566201));
#852=CARTESIAN_POINT('',(-180.935120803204,-18.7933717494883,2.52870812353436));
#853=CARTESIAN_POINT('',(-180.703783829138,-18.7933717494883,2.58505921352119));
#854=CARTESIAN_POINT('',(-180.60646039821,-18.7933717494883,2.60267961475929));
#855=CARTESIAN_POINT('',(-180.410419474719,-18.7933717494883,2.62619798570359));
#856=CARTESIAN_POINT('',(-180.311702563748,-18.7933717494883,2.63210070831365));
#857=CARTESIAN_POINT('',(-180.213,-18.7933717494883,2.63210155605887));
#858=B_SPLINE_CURVE_WITH_KNOTS('',3,(#776,#777,#778,#779,#780,#781,#782,#783,#784,#785,#786,
#787,#788,#789,#790,#791,#792,#793,#794,#795,#796,#797,#798,#799,#800,#801,#802,#803,#804,#805,
#806,#807,#808,#809,#810,#811,#812,#813,#814,#815,#816,#817,#818,#819,#820,#821,#822,#823,#824,
#825,#826,#827,#828,#829,#830,#831,#832,#833,#834,#835,#836,#837,#838,#839,#840,#841,#842,#843,
#844,#845,#846,#847,#848,#849,#850,#851,#852,#853,#854,#855,#856,#857),.UNSPECIFIED.,.T.,.F.,(4,
2,2,2,2,2,2,2,2,2,2,2,2,2,2,2,2,2,2,2,2,2,2,2,2,2,2,2,2,2,2,2,2,2,2,2,2,2,2,2,4),(0.,
0.252435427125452,0.505030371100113,0.922589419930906,1.34061341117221,1.75845502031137,
2.17619645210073,2.59397941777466,3.01177949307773,3.42957166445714,3.84736253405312,
4.26515372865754,4.68294557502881,5.10074261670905,5.5185286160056,5.93628782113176,
6.3541116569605,6.77205197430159,7.1896946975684,7.48576226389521,7.78170971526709,
8.03414514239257,8.28674008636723,8.70429913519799,9.12232312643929,9.54016473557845,
9.95790616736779,10.3756891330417,10.7934892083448,11.2112813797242,11.6290722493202,
12.0468634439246,12.4646552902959,12.8824523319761,13.3002383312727,13.7179975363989,
14.1358213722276,14.5537616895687,14.9714044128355,15.2674719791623,15.5634194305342),.UNSPECIFIED.);
#859=CARTESIAN_POINT('',(-180.213,-18.7933717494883,2.63210155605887));
#860=VERTEX_POINT('',#859);
#861=EDGE_CURVE('E61',#860,#860,#858,.T.);
#862=ORIENTED_EDGE('',*,*,#861,.F.);
#863=EDGE_LOOP('',(#862));
#864=FACE_BOUND('',#863,.T.);
#865=CARTESIAN_POINT('',(-199.263,-18.7933717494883,2.63210155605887));
#866=CARTESIAN_POINT('',(-199.178809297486,-18.7933717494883,2.63210227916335));
#867=CARTESIAN_POINT('',(-199.094629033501,-18.7933717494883,2.62780900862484));
#868=CARTESIAN_POINT('',(-198.927101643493,-18.7933717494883,2.61069058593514));
#869=CARTESIAN_POINT('',(-198.843755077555,-18.7933717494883,2.5978600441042));
#870=CARTESIAN_POINT('',(-198.624835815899,-18.7933717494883,2.55261481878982));
#871=CARTESIAN_POINT('',(-198.490703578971,-18.7933717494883,2.51288252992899));
#872=CARTESIAN_POINT('',(-198.230920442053,-18.7933717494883,2.41143114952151));
#873=CARTESIAN_POINT('',(-198.105279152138,-18.7933717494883,2.34968762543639));
#874=CARTESIAN_POINT('',(-197.866190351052,-18.7933717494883,2.20600089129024));
#875=CARTESIAN_POINT('',(-197.752737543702,-18.7933717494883,2.12406650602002));
#876=CARTESIAN_POINT('',(-197.541229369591,-18.7933717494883,1.9423343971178));
#877=CARTESIAN_POINT('',(-197.44317031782,-18.7933717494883,1.84254096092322));
#878=CARTESIAN_POINT('',(-197.265185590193,-18.7933717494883,1.62789843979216));
#879=CARTESIAN_POINT('',(-197.185261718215,-18.7933717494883,1.51304785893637));
#880=CARTESIAN_POINT('',(-197.045827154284,-18.7933717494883,1.27155407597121));
#881=CARTESIAN_POINT('',(-196.986317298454,-18.7933717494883,1.14491039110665));
#882=CARTESIAN_POINT('',(-196.889405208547,-18.7933717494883,0.883432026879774));
#883=CARTESIAN_POINT('',(-196.852002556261,-18.7933717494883,0.748597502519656));
#884=CARTESIAN_POINT('',(-196.800365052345,-18.7933717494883,0.474563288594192));
#885=CARTESIAN_POINT('',(-196.786130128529,-18.7933717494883,0.335363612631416));
#886=CARTESIAN_POINT('',(-196.781231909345,-18.7933717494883,0.0565500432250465));
#887=CARTESIAN_POINT('',(-196.790568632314,-18.7933717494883,-0.0830638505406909));
#888=CARTESIAN_POINT('',(-196.832548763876,-18.7933717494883,-0.358742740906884));
#889=CARTESIAN_POINT('',(-196.865192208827,-18.7933717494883,-0.494807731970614));
#890=CARTESIAN_POINT('',(-196.952859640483,-18.7933717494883,-0.759527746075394));
#891=CARTESIAN_POINT('',(-197.00788390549,-18.7933717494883,-0.888182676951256));
#892=CARTESIAN_POINT('',(-197.138749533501,-18.7933717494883,-1.13442527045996));
#893=CARTESIAN_POINT('',(-197.214590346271,-18.7933717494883,-1.25201322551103));
#894=CARTESIAN_POINT('',(-197.384930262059,-18.7933717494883,-1.47278061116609));
#895=CARTESIAN_POINT('',(-197.479428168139,-18.7933717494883,-1.5759609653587));
#896=CARTESIAN_POINT('',(-197.684423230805,-18.7933717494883,-1.76500863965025));
#897=CARTESIAN_POINT('',(-197.794922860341,-18.7933717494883,-1.85087327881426));
#898=CARTESIAN_POINT('',(-198.028790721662,-18.7933717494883,-2.00285138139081));
#899=CARTESIAN_POINT('',(-198.152162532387,-18.7933717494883,-2.06895933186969));
#900=CARTESIAN_POINT('',(-198.408210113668,-18.7933717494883,-2.17947999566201));
#901=CARTESIAN_POINT('',(-198.540879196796,-18.7933717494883,-2.22390812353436));
#902=CARTESIAN_POINT('',(-198.772216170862,-18.7933717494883,-2.28025921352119));
#903=CARTESIAN_POINT('',(-198.86953960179,-18.7933717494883,-2.29787961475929));
#904=CARTESIAN_POINT('',(-199.065580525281,-18.7933717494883,-2.32139798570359));
#905=CARTESIAN_POINT('',(-199.164297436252,-18.7933717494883,-2.32730070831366));
#906=CARTESIAN_POINT('',(-199.347190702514,-18.7933717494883,-2.32730227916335));
#907=CARTESIAN_POINT('',(-199.431370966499,-18.7933717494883,-2.32300900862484));
#908=CARTESIAN_POINT('',(-199.598898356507,-18.7933717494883,-2.30589058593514));
#909=CARTESIAN_POINT('',(-199.682244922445,-18.7933717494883,-2.2930600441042));
#910=CARTESIAN_POINT('',(-199.901164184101,-18.7933717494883,-2.24781481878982));
#911=CARTESIAN_POINT('',(-200.035296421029,-18.7933717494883,-2.20808252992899));
#912=CARTESIAN_POINT('',(-200.295079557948,-18.7933717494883,-2.10663114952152));
#913=CARTESIAN_POINT('',(-200.420720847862,-18.7933717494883,-2.0448876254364));
#914=CARTESIAN_POINT('',(-200.659809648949,-18.7933717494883,-1.90120089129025));
#915=CARTESIAN_POINT('',(-200.773262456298,-18.7933717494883,-1.81926650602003));
#916=CARTESIAN_POINT('',(-200.984770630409,-18.7933717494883,-1.6375343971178));
#917=CARTESIAN_POINT('',(-201.08282968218,-18.7933717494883,-1.53774096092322));
#918=CARTESIAN_POINT('',(-201.260814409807,-18.7933717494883,-1.32309843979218));
#919=CARTESIAN_POINT('',(-201.340738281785,-18.7933717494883,-1.20824785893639));
#920=CARTESIAN_POINT('',(-201.480172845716,-18.7933717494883,-0.966754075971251));
#921=CARTESIAN_POINT('',(-201.539682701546,-18.7933717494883,-0.840110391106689));
#922=CARTESIAN_POINT('',(-201.636594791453,-18.7933717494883,-0.578632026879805));
#923=CARTESIAN_POINT('',(-201.67399744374,-18.7933717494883,-0.443797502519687));
#924=CARTESIAN_POINT('',(-201.725634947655,-18.7933717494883,-0.16976328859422));
#925=CARTESIAN_POINT('',(-201.739869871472,-18.7933717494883,-0.0305636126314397));
#926=CARTESIAN_POINT('',(-201.744768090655,-18.7933717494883,0.248249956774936));
#927=CARTESIAN_POINT('',(-201.735431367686,-18.7933717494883,0.387863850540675));
#928=CARTESIAN_POINT('',(-201.693451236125,-18.7933717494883,0.663542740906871));
#929=CARTESIAN_POINT('',(-201.660807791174,-18.7933717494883,0.799607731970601));
#930=CARTESIAN_POINT('',(-201.573140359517,-18.7933717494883,1.06432774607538));
#931=CARTESIAN_POINT('',(-201.51811609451,-18.7933717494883,1.19298267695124));
#932=CARTESIAN_POINT('',(-201.387250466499,-18.7933717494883,1.43922527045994));
#933=CARTESIAN_POINT('',(-201.311409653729,-18.7933717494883,1.55681322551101));
#934=CARTESIAN_POINT('',(-201.141069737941,-18.7933717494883,1.77758061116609));
#935=CARTESIAN_POINT('',(-201.046571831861,-18.7933717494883,1.88076096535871));
#936=CARTESIAN_POINT('',(-200.841576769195,-18.7933717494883,2.06980863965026));
#937=CARTESIAN_POINT('',(-200.731077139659,-18.7933717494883,2.15567327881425));
#938=CARTESIAN_POINT('',(-200.497209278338,-18.7933717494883,2.30765138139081));
#939=CARTESIAN_POINT('',(-200.373837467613,-18.7933717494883,2.37375933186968));
#940=CARTESIAN_POINT('',(-200.117789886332,-18.7933717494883,2.48427999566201));
#941=CARTESIAN_POINT('',(-199.985120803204,-18.7933717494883,2.52870812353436));
#942=CARTESIAN_POINT('',(-199.753783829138,-18.7933717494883,2.58505921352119));
#943=CARTESIAN_POINT('',(-199.65646039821,-18.7933717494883,2.60267961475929));
#944=CARTESIAN_POINT('',(-199.460419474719,-18.7933717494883,2.62619798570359));
#945=CARTESIAN_POINT('',(-199.361702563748,-18.7933717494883,2.63210070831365));
#946=CARTESIAN_POINT('',(-199.263,-18.7933717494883,2.63210155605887));
#947=B_SPLINE_CURVE_WITH_KNOTS('',3,(#865,#866,#867,#868,#869,#870,#871,#872,#873,#874,#875,
#876,#877,#878,#879,#880,#881,#882,#883,#884,#885,#886,#887,#888,#889,#890,#891,#892,#893,#894,
#895,#896,#897,#898,#899,#900,#901,#902,#903,#904,#905,#906,#907,#908,#909,#910,#911,#912,#913,
#914,#915,#916,#917,#918,#919,#920,#921,#922,#923,#924,#925,#926,#927,#928,#929,#930,#931,#932,
#933,#934,#935,#936,#937,#938,#939,#940,#941,#942,#943,#944,#945,#946),.UNSPECIFIED.,.T.,.F.,(4,
2,2,2,2,2,2,2,2,2,2,2,2,2,2,2,2,2,2,2,2,2,2,2,2,2,2,2,2,2,2,2,2,2,2,2,2,2,2,2,4),(0.,
0.252435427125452,0.505030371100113,0.922589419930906,1.34061341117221,1.75845502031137,
2.17619645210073,2.59397941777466,3.01177949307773,3.42957166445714,3.84736253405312,
4.26515372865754,4.68294557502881,5.10074261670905,5.5185286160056,5.93628782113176,
6.3541116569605,6.77205197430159,7.1896946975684,7.48576226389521,7.78170971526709,
8.03414514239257,8.28674008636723,8.70429913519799,9.12232312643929,9.54016473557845,
9.95790616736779,10.3756891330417,10.7934892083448,11.2112813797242,11.6290722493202,
12.0468634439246,12.4646552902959,12.8824523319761,13.3002383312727,13.7179975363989,
14.1358213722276,14.5537616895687,14.9714044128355,15.2674719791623,15.5634194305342),.UNSPECIFIED.);
#948=CARTESIAN_POINT('',(-199.263,-18.7933717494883,2.63210155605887));
#949=VERTEX_POINT('',#948);
#950=EDGE_CURVE('E330',#949,#949,#947,.T.);
#951=ORIENTED_EDGE('',*,*,#950,.F.);
#952=EDGE_LOOP('',(#951));
#953=FACE_BOUND('',#952,.T.);
#954=CARTESIAN_POINT('',(-218.313,-18.7933717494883,2.63210155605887));
#955=CARTESIAN_POINT('',(-218.228809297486,-18.7933717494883,2.63210227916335));
#956=CARTESIAN_POINT('',(-218.144629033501,-18.7933717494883,2.62780900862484));
#957=CARTESIAN_POINT('',(-217.977101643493,-18.7933717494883,2.61069058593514));
#958=CARTESIAN_POINT('',(-217.893755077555,-18.7933717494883,2.5978600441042));
#959=CARTESIAN_POINT('',(-217.674835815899,-18.7933717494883,2.55261481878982));
#960=CARTESIAN_POINT('',(-217.540703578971,-18.7933717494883,2.51288252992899));
#961=CARTESIAN_POINT('',(-217.280920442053,-18.7933717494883,2.41143114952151));
#962=CARTESIAN_POINT('',(-217.155279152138,-18.7933717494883,2.34968762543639));
#963=CARTESIAN_POINT('',(-216.916190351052,-18.7933717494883,2.20600089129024));
#964=CARTESIAN_POINT('',(-216.802737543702,-18.7933717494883,2.12406650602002));
#965=CARTESIAN_POINT('',(-216.591229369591,-18.7933717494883,1.9423343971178));
#966=CARTESIAN_POINT('',(-216.49317031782,-18.7933717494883,1.84254096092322));
#967=CARTESIAN_POINT('',(-216.315185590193,-18.7933717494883,1.62789843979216));
#968=CARTESIAN_POINT('',(-216.235261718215,-18.7933717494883,1.51304785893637));
#969=CARTESIAN_POINT('',(-216.095827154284,-18.7933717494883,1.27155407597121));
#970=CARTESIAN_POINT('',(-216.036317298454,-18.7933717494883,1.14491039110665));
#971=CARTESIAN_POINT('',(-215.939405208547,-18.7933717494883,0.883432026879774));
#972=CARTESIAN_POINT('',(-215.902002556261,-18.7933717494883,0.748597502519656));
#973=CARTESIAN_POINT('',(-215.850365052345,-18.7933717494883,0.474563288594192));
#974=CARTESIAN_POINT('',(-215.836130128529,-18.7933717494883,0.335363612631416));
#975=CARTESIAN_POINT('',(-215.831231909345,-18.7933717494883,0.0565500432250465));
#976=CARTESIAN_POINT('',(-215.840568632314,-18.7933717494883,-0.0830638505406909));
#977=CARTESIAN_POINT('',(-215.882548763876,-18.7933717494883,-0.358742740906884));
#978=CARTESIAN_POINT('',(-215.915192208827,-18.7933717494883,-0.494807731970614));
#979=CARTESIAN_POINT('',(-216.002859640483,-18.7933717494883,-0.759527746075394));
#980=CARTESIAN_POINT('',(-216.05788390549,-18.7933717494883,-0.888182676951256));
#981=CARTESIAN_POINT('',(-216.188749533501,-18.7933717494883,-1.13442527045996));
#982=CARTESIAN_POINT('',(-216.264590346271,-18.7933717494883,-1.25201322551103));
#983=CARTESIAN_POINT('',(-216.434930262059,-18.7933717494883,-1.47278061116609));
#984=CARTESIAN_POINT('',(-216.529428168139,-18.7933717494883,-1.5759609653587));
#985=CARTESIAN_POINT('',(-216.734423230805,-18.7933717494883,-1.76500863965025));
#986=CARTESIAN_POINT('',(-216.844922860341,-18.7933717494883,-1.85087327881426));
#987=CARTESIAN_POINT('',(-217.078790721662,-18.7933717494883,-2.00285138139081));
#988=CARTESIAN_POINT('',(-217.202162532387,-18.7933717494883,-2.06895933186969));
#989=CARTESIAN_POINT('',(-217.458210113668,-18.7933717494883,-2.17947999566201));
#990=CARTESIAN_POINT('',(-217.590879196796,-18.7933717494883,-2.22390812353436));
#991=CARTESIAN_POINT('',(-217.822216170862,-18.7933717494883,-2.28025921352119));
#992=CARTESIAN_POINT('',(-217.91953960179,-18.7933717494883,-2.29787961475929));
#993=CARTESIAN_POINT('',(-218.115580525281,-18.7933717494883,-2.32139798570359));
#994=CARTESIAN_POINT('',(-218.214297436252,-18.7933717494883,-2.32730070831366));
#995=CARTESIAN_POINT('',(-218.397190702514,-18.7933717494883,-2.32730227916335));
#996=CARTESIAN_POINT('',(-218.481370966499,-18.7933717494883,-2.32300900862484));
#997=CARTESIAN_POINT('',(-218.648898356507,-18.7933717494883,-2.30589058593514));
#998=CARTESIAN_POINT('',(-218.732244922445,-18.7933717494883,-2.2930600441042));
#999=CARTESIAN_POINT('',(-218.951164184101,-18.7933717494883,-2.24781481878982));
#1000=CARTESIAN_POINT('',(-219.085296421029,-18.7933717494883,-2.20808252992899));
#1001=CARTESIAN_POINT('',(-219.345079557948,-18.7933717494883,-2.10663114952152));
#1002=CARTESIAN_POINT('',(-219.470720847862,-18.7933717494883,-2.0448876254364));
#1003=CARTESIAN_POINT('',(-219.709809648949,-18.7933717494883,-1.90120089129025));
#1004=CARTESIAN_POINT('',(-219.823262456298,-18.7933717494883,-1.81926650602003));
#1005=CARTESIAN_POINT('',(-220.034770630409,-18.7933717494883,-1.6375343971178));
#1006=CARTESIAN_POINT('',(-220.13282968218,-18.7933717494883,-1.53774096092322));
#1007=CARTESIAN_POINT('',(-220.310814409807,-18.7933717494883,-1.32309843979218));
#1008=CARTESIAN_POINT('',(-220.390738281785,-18.7933717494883,-1.20824785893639));
#1009=CARTESIAN_POINT('',(-220.530172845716,-18.7933717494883,-0.966754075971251));
#1010=CARTESIAN_POINT('',(-220.589682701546,-18.7933717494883,-0.840110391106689));
#1011=CARTESIAN_POINT('',(-220.686594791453,-18.7933717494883,-0.578632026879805));
#1012=CARTESIAN_POINT('',(-220.72399744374,-18.7933717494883,-0.443797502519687));
#1013=CARTESIAN_POINT('',(-220.775634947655,-18.7933717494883,-0.16976328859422));
#1014=CARTESIAN_POINT('',(-220.789869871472,-18.7933717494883,-0.0305636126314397));
#1015=CARTESIAN_POINT('',(-220.794768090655,-18.7933717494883,0.248249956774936));
#1016=CARTESIAN_POINT('',(-220.785431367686,-18.7933717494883,0.387863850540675));
#1017=CARTESIAN_POINT('',(-220.743451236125,-18.7933717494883,0.663542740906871));
#1018=CARTESIAN_POINT('',(-220.710807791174,-18.7933717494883,0.799607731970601));
#1019=CARTESIAN_POINT('',(-220.623140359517,-18.7933717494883,1.06432774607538));
#1020=CARTESIAN_POINT('',(-220.56811609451,-18.7933717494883,1.19298267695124));
#1021=CARTESIAN_POINT('',(-220.437250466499,-18.7933717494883,1.43922527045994));
#1022=CARTESIAN_POINT('',(-220.361409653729,-18.7933717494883,1.55681322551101));
#1023=CARTESIAN_POINT('',(-220.191069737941,-18.7933717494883,1.77758061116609));
#1024=CARTESIAN_POINT('',(-220.096571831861,-18.7933717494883,1.88076096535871));
#1025=CARTESIAN_POINT('',(-219.891576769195,-18.7933717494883,2.06980863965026));
#1026=CARTESIAN_POINT('',(-219.781077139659,-18.7933717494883,2.15567327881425));
#1027=CARTESIAN_POINT('',(-219.547209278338,-18.7933717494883,2.30765138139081));
#1028=CARTESIAN_POINT('',(-219.423837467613,-18.7933717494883,2.37375933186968));
#1029=CARTESIAN_POINT('',(-219.167789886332,-18.7933717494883,2.48427999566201));
#1030=CARTESIAN_POINT('',(-219.035120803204,-18.7933717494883,2.52870812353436));
#1031=CARTESIAN_POINT('',(-218.803783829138,-18.7933717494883,2.58505921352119));
#1032=CARTESIAN_POINT('',(-218.70646039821,-18.7933717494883,2.60267961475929));
#1033=CARTESIAN_POINT('',(-218.510419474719,-18.7933717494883,2.62619798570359));
#1034=CARTESIAN_POINT('',(-218.411702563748,-18.7933717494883,2.63210070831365));
#1035=CARTESIAN_POINT('',(-218.313,-18.7933717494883,2.63210155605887));
#1036=B_SPLINE_CURVE_WITH_KNOTS('',3,(#954,#955,#956,#957,#958,#959,#960,#961,#962,#963,#964,
#965,#966,#967,#968,#969,#970,#971,#972,#973,#974,#975,#976,#977,#978,#979,#980,#981,#982,#983,
#984,#985,#986,#987,#988,#989,#990,#991,#992,#993,#994,#995,#996,#997,#998,#999,#1000,#1001,
#1002,#1003,#1004,#1005,#1006,#1007,#1008,#1009,#1010,#1011,#1012,#1013,#1014,#1015,#1016,#1017,
#1018,#1019,#1020,#1021,#1022,#1023,#1024,#1025,#1026,#1027,#1028,#1029,#1030,#1031,#1032,#1033,
#1034,#1035),.UNSPECIFIED.,.T.,.F.,(4,2,2,2,2,2,2,2,2,2,2,2,2,2,2,2,2,2,2,2,2,2,2,2,2,2,2,2,2,2,
2,2,2,2,2,2,2,2,2,2,4),(0.,0.252435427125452,0.505030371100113,0.922589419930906,
1.34061341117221,1.75845502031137,2.17619645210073,2.59397941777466,3.01177949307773,
3.42957166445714,3.84736253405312,4.26515372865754,4.68294557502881,5.10074261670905,
5.5185286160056,5.93628782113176,6.3541116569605,6.77205197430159,7.1896946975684,
7.48576226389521,7.78170971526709,8.03414514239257,8.28674008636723,8.70429913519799,
9.12232312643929,9.54016473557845,9.95790616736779,10.3756891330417,10.7934892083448,
11.2112813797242,11.6290722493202,12.0468634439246,12.4646552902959,12.8824523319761,
13.3002383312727,13.7179975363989,14.1358213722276,14.5537616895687,14.9714044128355,
15.2674719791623,15.5634194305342),.UNSPECIFIED.);
#1037=CARTESIAN_POINT('',(-218.313,-18.7933717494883,2.63210155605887));
#1038=VERTEX_POINT('',#1037);
#1039=EDGE_CURVE('E613',#1038,#1038,#1036,.T.);
#1040=ORIENTED_EDGE('',*,*,#1039,.F.);
#1041=EDGE_LOOP('',(#1040));
#1042=FACE_BOUND('',#1041,.T.);
#1043=CARTESIAN_POINT('',(-237.363,-18.7933717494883,-2.32730155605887));
#1044=CARTESIAN_POINT('',(-237.447190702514,-18.7933717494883,-2.32730227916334));
#1045=CARTESIAN_POINT('',(-237.531370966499,-18.7933717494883,-2.32300900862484));
#1046=CARTESIAN_POINT('',(-237.698898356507,-18.7933717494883,-2.30589058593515));
#1047=CARTESIAN_POINT('',(-237.782244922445,-18.7933717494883,-2.2930600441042));
#1048=CARTESIAN_POINT('',(-238.001164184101,-18.7933717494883,-2.24781481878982));
#1049=CARTESIAN_POINT('',(-238.135296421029,-18.7933717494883,-2.20808252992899));
#1050=CARTESIAN_POINT('',(-238.395079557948,-18.7933717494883,-2.10663114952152));
#1051=CARTESIAN_POINT('',(-238.520720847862,-18.7933717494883,-2.0448876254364));
#1052=CARTESIAN_POINT('',(-238.759809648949,-18.7933717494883,-1.90120089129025));
#1053=CARTESIAN_POINT('',(-238.873262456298,-18.7933717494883,-1.81926650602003));
#1054=CARTESIAN_POINT('',(-239.084770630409,-18.7933717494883,-1.6375343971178));
#1055=CARTESIAN_POINT('',(-239.18282968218,-18.7933717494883,-1.53774096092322));
#1056=CARTESIAN_POINT('',(-239.360814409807,-18.7933717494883,-1.32309843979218));
#1057=CARTESIAN_POINT('',(-239.440738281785,-18.7933717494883,-1.20824785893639));
#1058=CARTESIAN_POINT('',(-239.580172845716,-18.7933717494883,-0.966754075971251));
#1059=CARTESIAN_POINT('',(-239.639682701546,-18.7933717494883,-0.840110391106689));
#1060=CARTESIAN_POINT('',(-239.736594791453,-18.7933717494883,-0.578632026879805));
#1061=CARTESIAN_POINT('',(-239.77399744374,-18.7933717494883,-0.443797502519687));
#1062=CARTESIAN_POINT('',(-239.825634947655,-18.7933717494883,-0.16976328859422));
#1063=CARTESIAN_POINT('',(-239.839869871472,-18.7933717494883,-0.0305636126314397));
#1064=CARTESIAN_POINT('',(-239.844768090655,-18.7933717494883,0.248249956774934));
#1065=CARTESIAN_POINT('',(-239.835431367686,-18.7933717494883,0.387863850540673));
#1066=CARTESIAN_POINT('',(-239.793451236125,-18.7933717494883,0.663542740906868));
#1067=CARTESIAN_POINT('',(-239.760807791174,-18.7933717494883,0.7996077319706));
#1068=CARTESIAN_POINT('',(-239.673140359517,-18.7933717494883,1.06432774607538));
#1069=CARTESIAN_POINT('',(-239.61811609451,-18.7933717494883,1.19298267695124));
#1070=CARTESIAN_POINT('',(-239.487250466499,-18.7933717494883,1.43922527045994));
#1071=CARTESIAN_POINT('',(-239.411409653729,-18.7933717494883,1.55681322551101));
#1072=CARTESIAN_POINT('',(-239.241069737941,-18.7933717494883,1.77758061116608));
#1073=CARTESIAN_POINT('',(-239.146571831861,-18.7933717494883,1.88076096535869));
#1074=CARTESIAN_POINT('',(-238.941576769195,-18.7933717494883,2.06980863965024));
#1075=CARTESIAN_POINT('',(-238.831077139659,-18.7933717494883,2.15567327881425));
#1076=CARTESIAN_POINT('',(-238.597209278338,-18.7933717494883,2.30765138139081));
#1077=CARTESIAN_POINT('',(-238.473837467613,-18.7933717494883,2.37375933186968));
#1078=CARTESIAN_POINT('',(-238.217789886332,-18.7933717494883,2.48427999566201));
#1079=CARTESIAN_POINT('',(-238.085120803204,-18.7933717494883,2.52870812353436));
#1080=CARTESIAN_POINT('',(-237.853783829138,-18.7933717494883,2.58505921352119));
#1081=CARTESIAN_POINT('',(-237.75646039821,-18.7933717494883,2.60267961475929));
#1082=CARTESIAN_POINT('',(-237.560419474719,-18.7933717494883,2.62619798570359));
#1083=CARTESIAN_POINT('',(-237.461702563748,-18.7933717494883,2.63210070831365));
#1084=CARTESIAN_POINT('',(-237.278809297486,-18.7933717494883,2.63210227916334));
#1085=CARTESIAN_POINT('',(-237.194629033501,-18.7933717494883,2.62780900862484));
#1086=CARTESIAN_POINT('',(-237.027101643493,-18.7933717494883,2.61069058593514));
#1087=CARTESIAN_POINT('',(-236.943755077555,-18.7933717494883,2.5978600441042));
#1088=CARTESIAN_POINT('',(-236.724835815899,-18.7933717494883,2.55261481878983));
#1089=CARTESIAN_POINT('',(-236.590703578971,-18.7933717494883,2.51288252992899));
#1090=CARTESIAN_POINT('',(-236.330920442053,-18.7933717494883,2.41143114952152));
#1091=CARTESIAN_POINT('',(-236.205279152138,-18.7933717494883,2.3496876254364));
#1092=CARTESIAN_POINT('',(-235.966190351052,-18.7933717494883,2.20600089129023));
#1093=CARTESIAN_POINT('',(-235.852737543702,-18.7933717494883,2.12406650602));
#1094=CARTESIAN_POINT('',(-235.641229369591,-18.7933717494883,1.94233439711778));
#1095=CARTESIAN_POINT('',(-235.54317031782,-18.7933717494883,1.84254096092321));
#1096=CARTESIAN_POINT('',(-235.365185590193,-18.7933717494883,1.62789843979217));
#1097=CARTESIAN_POINT('',(-235.285261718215,-18.7933717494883,1.51304785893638));
#1098=CARTESIAN_POINT('',(-235.145827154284,-18.7933717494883,1.27155407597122));
#1099=CARTESIAN_POINT('',(-235.086317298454,-18.7933717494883,1.14491039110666));
#1100=CARTESIAN_POINT('',(-234.989405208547,-18.7933717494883,0.883432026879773));
#1101=CARTESIAN_POINT('',(-234.952002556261,-18.7933717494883,0.748597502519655));
#1102=CARTESIAN_POINT('',(-234.900365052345,-18.7933717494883,0.474563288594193));
#1103=CARTESIAN_POINT('',(-234.886130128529,-18.7933717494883,0.335363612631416));
#1104=CARTESIAN_POINT('',(-234.881231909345,-18.7933717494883,0.0565500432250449));
#1105=CARTESIAN_POINT('',(-234.890568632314,-18.7933717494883,-0.083063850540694));
#1106=CARTESIAN_POINT('',(-234.932548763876,-18.7933717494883,-0.358742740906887));
#1107=CARTESIAN_POINT('',(-234.965192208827,-18.7933717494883,-0.494807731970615));
#1108=CARTESIAN_POINT('',(-235.052859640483,-18.7933717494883,-0.759527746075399));
#1109=CARTESIAN_POINT('',(-235.10788390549,-18.7933717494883,-0.888182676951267));
#1110=CARTESIAN_POINT('',(-235.238749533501,-18.7933717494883,-1.13442527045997));
#1111=CARTESIAN_POINT('',(-235.314590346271,-18.7933717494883,-1.25201322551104));
#1112=CARTESIAN_POINT('',(-235.484930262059,-18.7933717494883,-1.47278061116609));
#1113=CARTESIAN_POINT('',(-235.579428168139,-18.7933717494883,-1.5759609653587));
#1114=CARTESIAN_POINT('',(-235.784423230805,-18.7933717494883,-1.76500863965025));
#1115=CARTESIAN_POINT('',(-235.894922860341,-18.7933717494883,-1.85087327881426));
#1116=CARTESIAN_POINT('',(-236.128790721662,-18.7933717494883,-2.00285138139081));
#1117=CARTESIAN_POINT('',(-236.252162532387,-18.7933717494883,-2.06895933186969));
#1118=CARTESIAN_POINT('',(-236.508210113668,-18.7933717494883,-2.17947999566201));
#1119=CARTESIAN_POINT('',(-236.640879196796,-18.7933717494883,-2.22390812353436));
#1120=CARTESIAN_POINT('',(-236.872216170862,-18.7933717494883,-2.28025921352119));
#1121=CARTESIAN_POINT('',(-236.96953960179,-18.7933717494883,-2.29787961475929));
#1122=CARTESIAN_POINT('',(-237.165580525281,-18.7933717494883,-2.32139798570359));
#1123=CARTESIAN_POINT('',(-237.264297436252,-18.7933717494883,-2.32730070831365));
#1124=CARTESIAN_POINT('',(-237.363,-18.7933717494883,-2.32730155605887));
#1125=B_SPLINE_CURVE_WITH_KNOTS('',3,(#1043,#1044,#1045,#1046,#1047,#1048,#1049,#1050,#1051,
#1052,#1053,#1054,#1055,#1056,#1057,#1058,#1059,#1060,#1061,#1062,#1063,#1064,#1065,#1066,#1067,
#1068,#1069,#1070,#1071,#1072,#1073,#1074,#1075,#1076,#1077,#1078,#1079,#1080,#1081,#1082,#1083,
#1084,#1085,#1086,#1087,#1088,#1089,#1090,#1091,#1092,#1093,#1094,#1095,#1096,#1097,#1098,#1099,
#1100,#1101,#1102,#1103,#1104,#1105,#1106,#1107,#1108,#1109,#1110,#1111,#1112,#1113,#1114,#1115,
#1116,#1117,#1118,#1119,#1120,#1121,#1122,#1123,#1124),.UNSPECIFIED.,.T.,.F.,(4,2,2,2,2,2,2,2,2,
2,2,2,2,2,2,2,2,2,2,2,2,2,2,2,2,2,2,2,2,2,2,2,2,2,2,2,2,2,2,2,4),(0.,0.252435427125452,
0.505030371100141,0.922589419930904,1.34061341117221,1.75845502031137,2.17619645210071,
2.59397941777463,3.0117794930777,3.42957166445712,3.8473625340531,4.26515372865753,
4.6829455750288,5.10074261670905,5.5185286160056,5.93628782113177,6.35411165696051,
6.77205197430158,7.18969469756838,7.4857622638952,7.7817097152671,8.03414514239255,
8.28674008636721,8.70429913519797,9.12232312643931,9.54016473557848,9.95790616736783,
10.3756891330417,10.7934892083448,11.2112813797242,11.6290722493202,12.0468634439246,
12.4646552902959,12.8824523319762,13.3002383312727,13.7179975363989,14.1358213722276,
14.5537616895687,14.9714044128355,15.2674719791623,15.5634194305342),.UNSPECIFIED.);
#1126=CARTESIAN_POINT('',(-237.363,-18.7933717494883,-2.32730155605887));
#1127=VERTEX_POINT('',#1126);
#1128=EDGE_CURVE('E337',#1127,#1127,#1125,.T.);
#1129=ORIENTED_EDGE('',*,*,#1128,.F.);
#1130=EDGE_LOOP('',(#1129));
#1131=FACE_BOUND('',#1130,.T.);
#1132=DIRECTION('',(0.,0.,1.));
#1133=VECTOR('',#1132,1.);
#1134=CARTESIAN_POINT('',(-135.763,-18.7933717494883,2.63210155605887));
#1135=LINE('',#1134,#1133);
#1136=CARTESIAN_POINT('',(-135.763,-18.7933717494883,-3.6576));
#1137=VERTEX_POINT('',#1136);
#1138=CARTESIAN_POINT('',(-135.763,-18.7933717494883,3.96240000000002));
#1139=VERTEX_POINT('',#1138);
#1140=EDGE_CURVE('E69',#1137,#1139,#1135,.T.);
#1141=ORIENTED_EDGE('',*,*,#1140,.F.);
#1142=DIRECTION('',(1.,0.,0.));
#1143=VECTOR('',#1142,1.);
#1144=CARTESIAN_POINT('',(-135.763,-18.7933717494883,-3.6576));
#1145=LINE('',#1144,#1143);
#1146=CARTESIAN_POINT('',(-243.713,-18.7933717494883,-3.6576));
#1147=VERTEX_POINT('',#1146);
#1148=EDGE_CURVE('E98',#1147,#1137,#1145,.T.);
#1149=ORIENTED_EDGE('',*,*,#1148,.F.);
#1150=DIRECTION('',(0.,0.,-1.));
#1151=VECTOR('',#1150,1.);
#1152=CARTESIAN_POINT('',(-243.713,-18.7933717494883,-2.32730155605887));
#1153=LINE('',#1152,#1151);
#1154=CARTESIAN_POINT('',(-243.713,-18.7933717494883,3.9624));
#1155=VERTEX_POINT('',#1154);
#1156=EDGE_CURVE('E122',#1155,#1147,#1153,.T.);
#1157=ORIENTED_EDGE('',*,*,#1156,.F.);
#1158=DIRECTION('',(-1.,0.,0.));
#1159=VECTOR('',#1158,1.);
#1160=CARTESIAN_POINT('',(-239.842701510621,-18.7933717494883,3.96240000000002));
#1161=LINE('',#1160,#1159);
#1162=EDGE_CURVE('E99',#1139,#1155,#1161,.T.);
#1163=ORIENTED_EDGE('',*,*,#1162,.F.);
#1164=EDGE_LOOP('',(#1141,#1149,#1157,#1163));
#1165=FACE_BOUND('',#1164,.T.);
#1166=ADVANCED_FACE('F95',(#686,#775,#864,#953,#1042,#1131,#1165),#597,.F.);
#1167=CARTESIAN_POINT('',(-161.163,-19.1743717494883,0.1524));
#1168=DIRECTION('',(0.,0.,1.));
#1169=DIRECTION('',(0.,1.,0.));
#1170=AXIS2_PLACEMENT_3D('',#1167,#1168,#1169);
#1171=SPHERICAL_SURFACE('',#1170,2.50880067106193);
#1172=ORIENTED_EDGE('',*,*,#465,.T.);
#1173=EDGE_LOOP('',(#1172));
#1174=FACE_BOUND('',#1173,.T.);
#1175=ADVANCED_FACE('F47',(#1174),#1171,.T.);
#1176=CARTESIAN_POINT('',(-199.263,-19.1743717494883,0.1524));
#1177=DIRECTION('',(0.,0.,1.));
#1178=DIRECTION('',(0.,1.,0.));
#1179=AXIS2_PLACEMENT_3D('',#1176,#1177,#1178);
#1180=SPHERICAL_SURFACE('',#1179,2.50880067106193);
#1181=ORIENTED_EDGE('',*,*,#287,.T.);
#1182=EDGE_LOOP('',(#1181));
#1183=FACE_BOUND('',#1182,.T.);
#1184=ADVANCED_FACE('F263',(#1183),#1180,.T.);
#1185=CARTESIAN_POINT('',(-237.363,-19.1743717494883,0.1524));
#1186=DIRECTION('',(0.,0.,1.));
#1187=DIRECTION('',(0.,1.,0.));
#1188=AXIS2_PLACEMENT_3D('',#1185,#1186,#1187);
#1189=SPHERICAL_SURFACE('',#1188,2.50880067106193);
#1190=ORIENTED_EDGE('',*,*,#109,.T.);
#1191=EDGE_LOOP('',(#1190));
#1192=FACE_BOUND('',#1191,.T.);
#1193=ADVANCED_FACE('F306',(#1192),#1189,.T.);
#1194=CARTESIAN_POINT('',(-218.313,-19.1743717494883,0.1524));
#1195=DIRECTION('',(0.,0.,1.));
#1196=DIRECTION('',(0.,1.,0.));
#1197=AXIS2_PLACEMENT_3D('',#1194,#1195,#1196);
#1198=SPHERICAL_SURFACE('',#1197,2.50880067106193);
#1199=ORIENTED_EDGE('',*,*,#198,.T.);
#1200=EDGE_LOOP('',(#1199));
#1201=FACE_BOUND('',#1200,.T.);
#1202=ADVANCED_FACE('F301',(#1201),#1198,.T.);
#1203=CARTESIAN_POINT('',(-180.213,-19.1743717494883,0.1524));
#1204=DIRECTION('',(0.,0.,1.));
#1205=DIRECTION('',(0.,1.,0.));
#1206=AXIS2_PLACEMENT_3D('',#1203,#1204,#1205);
#1207=SPHERICAL_SURFACE('',#1206,2.50880067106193);
#1208=ORIENTED_EDGE('',*,*,#376,.T.);
#1209=EDGE_LOOP('',(#1208));
#1210=FACE_BOUND('',#1209,.T.);
#1211=ADVANCED_FACE('F305',(#1210),#1207,.T.);
#1212=CARTESIAN_POINT('',(-142.113,-19.1743717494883,0.1524));
#1213=DIRECTION('',(0.,0.,1.));
#1214=DIRECTION('',(0.,1.,0.));
#1215=AXIS2_PLACEMENT_3D('',#1212,#1213,#1214);
#1216=SPHERICAL_SURFACE('',#1215,2.50880067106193);
#1217=ORIENTED_EDGE('',*,*,#554,.T.);
#1218=EDGE_LOOP('',(#1217));
#1219=FACE_BOUND('',#1218,.T.);
#1220=ADVANCED_FACE('F274',(#1219),#1216,.T.);
#1221=CARTESIAN_POINT('',(-161.163,-19.1743717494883,0.1524));
#1222=DIRECTION('',(0.,0.,1.));
#1223=DIRECTION('',(0.,1.,0.));
#1224=AXIS2_PLACEMENT_3D('',#1221,#1222,#1223);
#1225=SPHERICAL_SURFACE('',#1224,2.50880067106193);
#1226=ORIENTED_EDGE('',*,*,#772,.T.);
#1227=EDGE_LOOP('',(#1226));
#1228=FACE_BOUND('',#1227,.T.);
#1229=ADVANCED_FACE('F270',(#1228),#1225,.T.);
#1230=CARTESIAN_POINT('',(-199.263,-19.1743717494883,0.1524));
#1231=DIRECTION('',(0.,0.,1.));
#1232=DIRECTION('',(0.,1.,0.));
#1233=AXIS2_PLACEMENT_3D('',#1230,#1231,#1232);
#1234=SPHERICAL_SURFACE('',#1233,2.50880067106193);
#1235=ORIENTED_EDGE('',*,*,#950,.T.);
#1236=EDGE_LOOP('',(#1235));
#1237=FACE_BOUND('',#1236,.T.);
#1238=ADVANCED_FACE('F322',(#1237),#1234,.T.);
#1239=CARTESIAN_POINT('',(-237.363,-19.1743717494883,0.1524));
#1240=DIRECTION('',(0.,0.,1.));
#1241=DIRECTION('',(0.,1.,0.));
#1242=AXIS2_PLACEMENT_3D('',#1239,#1240,#1241);
#1243=SPHERICAL_SURFACE('',#1242,2.50880067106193);
#1244=ORIENTED_EDGE('',*,*,#1128,.T.);
#1245=EDGE_LOOP('',(#1244));
#1246=FACE_BOUND('',#1245,.T.);
#1247=ADVANCED_FACE('F326',(#1246),#1243,.T.);
#1248=CARTESIAN_POINT('',(-218.313,-19.1743717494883,0.1524));
#1249=DIRECTION('',(0.,0.,1.));
#1250=DIRECTION('',(0.,1.,0.));
#1251=AXIS2_PLACEMENT_3D('',#1248,#1249,#1250);
#1252=SPHERICAL_SURFACE('',#1251,2.50880067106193);
#1253=ORIENTED_EDGE('',*,*,#1039,.T.);
#1254=EDGE_LOOP('',(#1253));
#1255=FACE_BOUND('',#1254,.T.);
#1256=ADVANCED_FACE('F416',(#1255),#1252,.T.);
#1257=CARTESIAN_POINT('',(-180.213,-19.1743717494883,0.1524));
#1258=DIRECTION('',(0.,0.,1.));
#1259=DIRECTION('',(0.,1.,0.));
#1260=AXIS2_PLACEMENT_3D('',#1257,#1258,#1259);
#1261=SPHERICAL_SURFACE('',#1260,2.50880067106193);
#1262=ORIENTED_EDGE('',*,*,#861,.T.);
#1263=EDGE_LOOP('',(#1262));
#1264=FACE_BOUND('',#1263,.T.);
#1265=ADVANCED_FACE('F141',(#1264),#1261,.T.);
#1266=CARTESIAN_POINT('',(-142.113,-19.1743717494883,0.1524));
#1267=DIRECTION('',(0.,0.,1.));
#1268=DIRECTION('',(0.,1.,0.));
#1269=AXIS2_PLACEMENT_3D('',#1266,#1267,#1268);
#1270=SPHERICAL_SURFACE('',#1269,2.50880067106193);
#1271=ORIENTED_EDGE('',*,*,#683,.T.);
#1272=EDGE_LOOP('',(#1271));
#1273=FACE_BOUND('',#1272,.T.);
#1274=ADVANCED_FACE('F136',(#1273),#1270,.T.);
#1275=CARTESIAN_POINT('',(-135.763,0.,0.));
#1276=DIRECTION('',(-1.,0.,0.));
#1277=DIRECTION('',(0.,0.,1.));
#1278=AXIS2_PLACEMENT_3D('',#1275,#1276,#1277);
#1279=PLANE('',#1278);
#1280=ORIENTED_EDGE('',*,*,#1140,.T.);
#1281=DIRECTION('',(0.,1.,0.));
#1282=VECTOR('',#1281,1.);
#1283=CARTESIAN_POINT('',(-135.763,-18.7933717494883,3.96240000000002));
#1284=LINE('',#1283,#1282);
#1285=EDGE_CURVE('E127',#581,#1139,#1284,.T.);
#1286=ORIENTED_EDGE('',*,*,#1285,.F.);
#1287=ORIENTED_EDGE('',*,*,#582,.T.);
#1288=DIRECTION('',(0.,-1.,0.));
#1289=VECTOR('',#1288,1.);
#1290=CARTESIAN_POINT('',(-135.763,-19.5553717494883,-3.6576));
#1291=LINE('',#1290,#1289);
#1292=EDGE_CURVE('E102',#1137,#573,#1291,.T.);
#1293=ORIENTED_EDGE('',*,*,#1292,.F.);
#1294=EDGE_LOOP('',(#1280,#1286,#1287,#1293));
#1295=FACE_BOUND('',#1294,.T.);
#1296=ADVANCED_FACE('F103',(#1295),#1279,.F.);
#1297=CARTESIAN_POINT('',(0.,0.,3.96240000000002));
#1298=DIRECTION('',(0.,0.,-1.));
#1299=DIRECTION('',(-1.,0.,0.));
#1300=AXIS2_PLACEMENT_3D('',#1297,#1298,#1299);
#1301=PLANE('',#1300);
#1302=ORIENTED_EDGE('',*,*,#588,.T.);
#1303=ORIENTED_EDGE('',*,*,#1285,.T.);
#1304=ORIENTED_EDGE('',*,*,#1162,.T.);
#1305=DIRECTION('',(0.,1.,0.));
#1306=VECTOR('',#1305,1.);
#1307=CARTESIAN_POINT('',(-243.713,-18.7933717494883,3.9624));
#1308=LINE('',#1307,#1306);
#1309=EDGE_CURVE('E119',#565,#1155,#1308,.T.);
#1310=ORIENTED_EDGE('',*,*,#1309,.F.);
#1311=EDGE_LOOP('',(#1302,#1303,#1304,#1310));
#1312=FACE_BOUND('',#1311,.T.);
#1313=ADVANCED_FACE('F375',(#1312),#1301,.F.);
#1314=CARTESIAN_POINT('',(-243.713,0.,0.));
#1315=DIRECTION('',(1.,0.,0.));
#1316=DIRECTION('',(0.,0.,-1.));
#1317=AXIS2_PLACEMENT_3D('',#1314,#1315,#1316);
#1318=PLANE('',#1317);
#1319=ORIENTED_EDGE('',*,*,#566,.T.);
#1320=ORIENTED_EDGE('',*,*,#1309,.T.);
#1321=ORIENTED_EDGE('',*,*,#1156,.T.);
#1322=DIRECTION('',(0.,1.,0.));
#1323=VECTOR('',#1322,1.);
#1324=CARTESIAN_POINT('',(-243.713,-18.7933717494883,-3.6576));
#1325=LINE('',#1324,#1323);
#1326=EDGE_CURVE('E111',#563,#1147,#1325,.T.);
#1327=ORIENTED_EDGE('',*,*,#1326,.F.);
#1328=EDGE_LOOP('',(#1319,#1320,#1321,#1327));
#1329=FACE_BOUND('',#1328,.T.);
#1330=ADVANCED_FACE('F373',(#1329),#1318,.F.);
#1331=CARTESIAN_POINT('',(0.,0.,-3.6576));
#1332=DIRECTION('',(0.,0.,1.));
#1333=DIRECTION('',(1.,0.,0.));
#1334=AXIS2_PLACEMENT_3D('',#1331,#1332,#1333);
#1335=PLANE('',#1334);
#1336=ORIENTED_EDGE('',*,*,#1148,.T.);
#1337=ORIENTED_EDGE('',*,*,#1292,.T.);
#1338=ORIENTED_EDGE('',*,*,#574,.T.);
#1339=ORIENTED_EDGE('',*,*,#1326,.T.);
#1340=EDGE_LOOP('',(#1336,#1337,#1338,#1339));
#1341=FACE_BOUND('',#1340,.T.);
#1342=ADVANCED_FACE('F109',(#1341),#1335,.F.);
#1343=CLOSED_SHELL('',(#592,#1166,#1175,#1184,#1193,#1202,#1211,#1220,#1229,#1238,#1247,#1256,
#1265,#1274,#1296,#1313,#1330,#1342));
#1344=MANIFOLD_SOLID_BREP('B2',#1343);
#1345=ADVANCED_BREP_SHAPE_REPRESENTATION('',(#18,#1344),#14);
#1346=SHAPE_DEFINITION_REPRESENTATION(#9,#1345);
ENDSEC;
END-ISO-10303-21;
